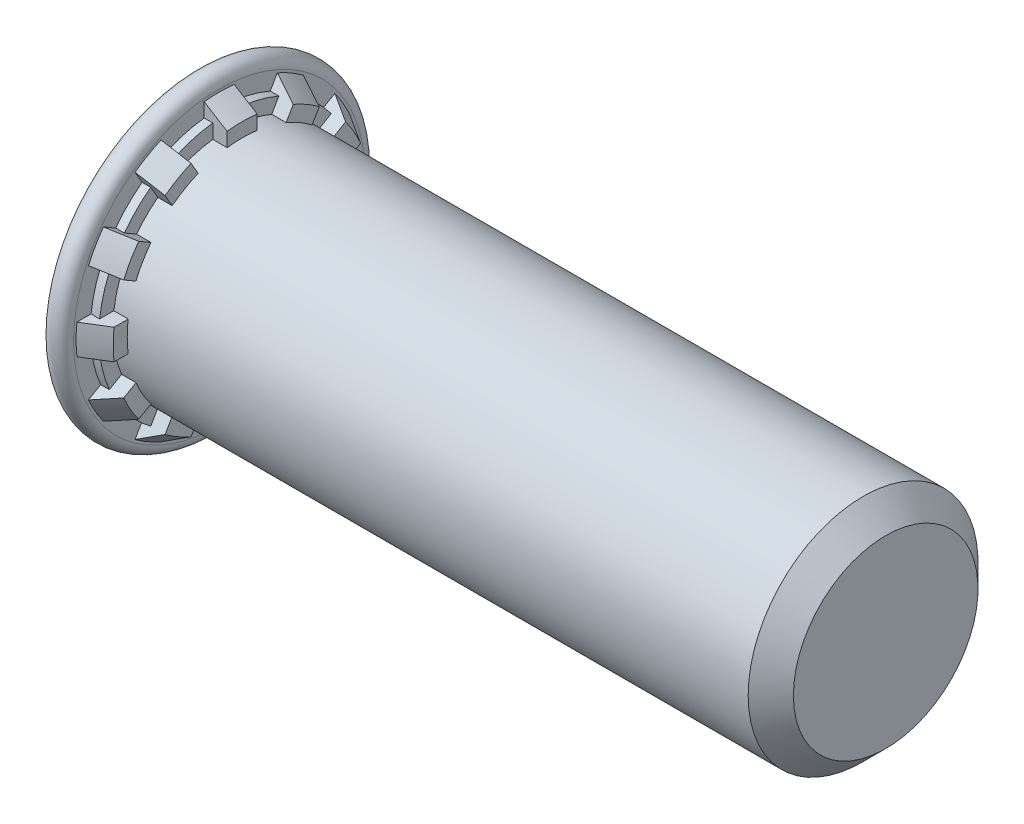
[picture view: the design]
ISO-10303-21;
HEADER;
FILE_DESCRIPTION(('STEP AP214'),'2;1');
FILE_NAME('part.step','',(''),(''),'','','');
FILE_SCHEMA(('AUTOMOTIVE_DESIGN { 1 0 10303 214 1 1 1 1 }'));
ENDSEC;
DATA;
#1=APPLICATION_CONTEXT('core data for automotive mechanical design processes');
#2=APPLICATION_PROTOCOL_DEFINITION('international standard','automotive_design',2000,#1);
#3=PRODUCT_CONTEXT('',#1,'mechanical');
#4=PRODUCT('Part','Part','',(#3));
#5=PRODUCT_RELATED_PRODUCT_CATEGORY('part','',(#4));
#6=PRODUCT_DEFINITION_FORMATION('','',#4);
#7=PRODUCT_DEFINITION_CONTEXT('part definition',#1,'design');
#8=PRODUCT_DEFINITION('design','',#6,#7);
#9=PRODUCT_DEFINITION_SHAPE('','',#8);
#10=(LENGTH_UNIT() NAMED_UNIT(*) SI_UNIT(.MILLI.,.METRE.));
#11=(NAMED_UNIT(*) PLANE_ANGLE_UNIT() SI_UNIT($,.RADIAN.));
#12=(NAMED_UNIT(*) SI_UNIT($,.STERADIAN.) SOLID_ANGLE_UNIT());
#13=UNCERTAINTY_MEASURE_WITH_UNIT(LENGTH_MEASURE(1.E-05),#10,'distance_accuracy_value','');
#14=(GEOMETRIC_REPRESENTATION_CONTEXT(3) GLOBAL_UNCERTAINTY_ASSIGNED_CONTEXT((#13)) GLOBAL_UNIT_ASSIGNED_CONTEXT((#10,
#11,#12)) REPRESENTATION_CONTEXT('',''));
#15=CARTESIAN_POINT('',(0.,0.,0.));
#16=DIRECTION('',(0.,0.,1.));
#17=DIRECTION('',(1.,0.,0.));
#18=AXIS2_PLACEMENT_3D('',#15,#16,#17);
#19=CARTESIAN_POINT('',(0.6,0.,0.));
#20=DIRECTION('',(-1.,0.,0.));
#21=DIRECTION('',(0.,0.,1.));
#22=AXIS2_PLACEMENT_3D('',#19,#20,#21);
#23=CONICAL_SURFACE('',#22,3.735,0.54956001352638);
#24=CARTESIAN_POINT('',(0.6,0.,0.));
#25=DIRECTION('',(-1.,0.,0.));
#26=DIRECTION('',(0.,0.,1.));
#27=AXIS2_PLACEMENT_3D('',#24,#25,#26);
#28=CIRCLE('',#27,3.735);
#29=CARTESIAN_POINT('',(0.6,3.02098991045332,2.19632533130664));
#30=VERTEX_POINT('',#29);
#31=CARTESIAN_POINT('',(0.6,3.41256848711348,1.51809134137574));
#32=VERTEX_POINT('',#31);
#33=EDGE_CURVE('E963',#30,#32,#28,.T.);
#34=ORIENTED_EDGE('',*,*,#33,.F.);
#35=CARTESIAN_POINT('',(1.2002,2.70066079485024,2.01138323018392));
#36=CARTESIAN_POINT('',(1.07508025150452,2.76747981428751,2.04996120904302));
#37=CARTESIAN_POINT('',(0.94994691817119,2.83427974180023,2.08852816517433));
#38=CARTESIAN_POINT('',(0.74980487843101,2.941079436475,2.15018899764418));
#39=CARTESIAN_POINT('',(0.67480487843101,2.98109143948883,2.17328993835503));
#40=CARTESIAN_POINT('',(0.5998,3.0210965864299,2.19638692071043));
#41=B_SPLINE_CURVE_WITH_KNOTS('',3,(#35,#36,#37,#38,#39,#40),.UNSPECIFIED.,.F.,.F.,(4,2,4),(0.,
0.44098970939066,0.705255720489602),.UNSPECIFIED.);
#42=CARTESIAN_POINT('',(1.2,2.70076760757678,2.01144489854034));
#43=VERTEX_POINT('',#42);
#44=EDGE_CURVE('E964',#43,#30,#41,.T.);
#45=ORIENTED_EDGE('',*,*,#44,.F.);
#46=CARTESIAN_POINT('',(1.2,0.,0.));
#47=DIRECTION('',(-1.,0.,0.));
#48=DIRECTION('',(0.,0.,1.));
#49=AXIS2_PLACEMENT_3D('',#46,#47,#48);
#50=CIRCLE('',#49,3.3675);
#51=CARTESIAN_POINT('',(1.2,3.09234618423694,1.33321090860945));
#52=VERTEX_POINT('',#51);
#53=EDGE_CURVE('E1232',#43,#52,#50,.T.);
#54=ORIENTED_EDGE('',*,*,#53,.T.);
#55=CARTESIAN_POINT('',(0.5998,3.41267516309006,1.51815293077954));
#56=CARTESIAN_POINT('',(0.67480487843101,3.37267001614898,1.49505594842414));
#57=CARTESIAN_POINT('',(0.74980487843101,3.33265801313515,1.47195500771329));
#58=CARTESIAN_POINT('',(0.94994691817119,3.22585831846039,1.41029417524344));
#59=CARTESIAN_POINT('',(1.07508025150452,3.15905839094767,1.37172721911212));
#60=CARTESIAN_POINT('',(1.2002,3.0922393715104,1.33314924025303));
#61=B_SPLINE_CURVE_WITH_KNOTS('',3,(#55,#56,#57,#58,#59,#60),.UNSPECIFIED.,.F.,.F.,(4,2,4),(0.,
0.264266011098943,0.705255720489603),.UNSPECIFIED.);
#62=EDGE_CURVE('E855',#32,#52,#61,.T.);
#63=ORIENTED_EDGE('',*,*,#62,.F.);
#64=EDGE_LOOP('',(#34,#45,#54,#63));
#65=FACE_BOUND('',#64,.T.);
#66=ADVANCED_FACE('F39',(#65),#23,.T.);
#67=CARTESIAN_POINT('',(0.5998,2.19638692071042,3.02109658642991));
#68=CARTESIAN_POINT('',(0.674804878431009,2.17328993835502,2.98109143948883));
#69=CARTESIAN_POINT('',(0.74980487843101,2.15018899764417,2.941079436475));
#70=CARTESIAN_POINT('',(0.94994691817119,2.08852816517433,2.83427974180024));
#71=CARTESIAN_POINT('',(1.07508025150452,2.04996120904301,2.76747981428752));
#72=CARTESIAN_POINT('',(1.2002,2.01138323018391,2.70066079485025));
#73=B_SPLINE_CURVE_WITH_KNOTS('',3,(#67,#68,#69,#70,#71,#72),.UNSPECIFIED.,.F.,.F.,(4,2,4),(0.,
0.264266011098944,0.705255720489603),.UNSPECIFIED.);
#74=CARTESIAN_POINT('',(0.6,2.19632533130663,3.02098991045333));
#75=VERTEX_POINT('',#74);
#76=CARTESIAN_POINT('',(1.2,2.01144489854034,2.70076760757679));
#77=VERTEX_POINT('',#76);
#78=EDGE_CURVE('E1268',#75,#77,#73,.T.);
#79=ORIENTED_EDGE('',*,*,#78,.F.);
#80=CARTESIAN_POINT('',(0.6,1.51809134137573,3.41256848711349));
#81=VERTEX_POINT('',#80);
#82=EDGE_CURVE('E501',#81,#75,#28,.T.);
#83=ORIENTED_EDGE('',*,*,#82,.F.);
#84=CARTESIAN_POINT('',(1.2002,1.33314924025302,3.0922393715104));
#85=CARTESIAN_POINT('',(1.07508025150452,1.37172721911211,3.15905839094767));
#86=CARTESIAN_POINT('',(0.94994691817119,1.41029417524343,3.22585831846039));
#87=CARTESIAN_POINT('',(0.749804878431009,1.47195500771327,3.33265801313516));
#88=CARTESIAN_POINT('',(0.674804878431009,1.49505594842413,3.37267001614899));
#89=CARTESIAN_POINT('',(0.5998,1.51815293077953,3.41267516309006));
#90=B_SPLINE_CURVE_WITH_KNOTS('',3,(#84,#85,#86,#87,#88,#89),.UNSPECIFIED.,.F.,.F.,(4,2,4),(0.,
0.440989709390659,0.705255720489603),.UNSPECIFIED.);
#91=CARTESIAN_POINT('',(1.2,1.33321090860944,3.09234618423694));
#92=VERTEX_POINT('',#91);
#93=EDGE_CURVE('E1013',#92,#81,#90,.T.);
#94=ORIENTED_EDGE('',*,*,#93,.F.);
#95=EDGE_CURVE('E1237',#92,#77,#50,.T.);
#96=ORIENTED_EDGE('',*,*,#95,.T.);
#97=EDGE_LOOP('',(#79,#83,#94,#96));
#98=FACE_BOUND('',#97,.T.);
#99=ADVANCED_FACE('F952',(#98),#23,.T.);
#100=CARTESIAN_POINT('',(-0.296527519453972,0.391578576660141,4.26618998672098));
#101=CARTESIAN_POINT('',(-0.286159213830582,0.391578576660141,4.25981269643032));
#102=CARTESIAN_POINT('',(-0.275790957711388,0.391578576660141,4.25343532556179));
#103=CARTESIAN_POINT('',(0.213231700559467,0.391578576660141,3.95263889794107));
#104=CARTESIAN_POINT('',(0.691778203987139,0.391578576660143,3.65804424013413));
#105=CARTESIAN_POINT('',(1.40926693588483,0.391578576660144,3.21561509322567));
#106=CARTESIAN_POINT('',(1.64837471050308,0.391578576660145,3.0680491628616));
#107=CARTESIAN_POINT('',(2.12640919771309,0.391578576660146,2.77262408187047));
#108=CARTESIAN_POINT('',(2.36533591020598,0.391578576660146,2.62476493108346));
#109=CARTESIAN_POINT('',(2.60413661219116,0.391578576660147,2.47670216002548));
#110=B_SPLINE_CURVE_WITH_KNOTS('',3,(#100,#101,#102,#103,#104,#105,#106,#107,#108,#109),
.UNSPECIFIED.,.F.,.F.,(4,2,2,2,4),(0.,0.0365177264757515,1.72238057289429,2.56531223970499,
3.40824436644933),.UNSPECIFIED.);
#111=CARTESIAN_POINT('',(0.6,0.391578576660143,3.71441667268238));
#112=VERTEX_POINT('',#111);
#113=CARTESIAN_POINT('',(1.2,0.391578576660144,3.34465580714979));
#114=VERTEX_POINT('',#113);
#115=EDGE_CURVE('E1009',#112,#114,#110,.T.);
#116=ORIENTED_EDGE('',*,*,#115,.F.);
#117=CARTESIAN_POINT('',(0.6,-0.391578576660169,3.71441667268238));
#118=VERTEX_POINT('',#117);
#119=EDGE_CURVE('E970',#118,#112,#28,.T.);
#120=ORIENTED_EDGE('',*,*,#119,.F.);
#121=CARTESIAN_POINT('',(2.60413661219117,-0.391578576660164,2.47670216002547));
#122=CARTESIAN_POINT('',(2.36533591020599,-0.391578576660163,2.62476493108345));
#123=CARTESIAN_POINT('',(2.12640919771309,-0.391578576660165,2.77262408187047));
#124=CARTESIAN_POINT('',(1.64837471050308,-0.391578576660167,3.0680491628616));
#125=CARTESIAN_POINT('',(1.40926693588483,-0.391578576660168,3.21561509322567));
#126=CARTESIAN_POINT('',(0.691778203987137,-0.391578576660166,3.65804424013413));
#127=CARTESIAN_POINT('',(0.213231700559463,-0.391578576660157,3.95263889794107));
#128=CARTESIAN_POINT('',(-0.275790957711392,-0.391578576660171,4.25343532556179));
#129=CARTESIAN_POINT('',(-0.286159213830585,-0.391578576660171,4.25981269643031));
#130=CARTESIAN_POINT('',(-0.296527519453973,-0.391578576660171,4.26618998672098));
#131=B_SPLINE_CURVE_WITH_KNOTS('',3,(#121,#122,#123,#124,#125,#126,#127,#128,#129,#130),
.UNSPECIFIED.,.F.,.F.,(4,2,2,2,4),(0.,0.842932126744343,1.68586379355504,3.37172663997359,
3.40824436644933),.UNSPECIFIED.);
#132=CARTESIAN_POINT('',(1.2,-0.391578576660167,3.34465580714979));
#133=VERTEX_POINT('',#132);
#134=EDGE_CURVE('E1007',#133,#118,#131,.T.);
#135=ORIENTED_EDGE('',*,*,#134,.F.);
#136=EDGE_CURVE('E1010',#133,#114,#50,.T.);
#137=ORIENTED_EDGE('',*,*,#136,.T.);
#138=EDGE_LOOP('',(#116,#120,#135,#137));
#139=FACE_BOUND('',#138,.T.);
#140=ADVANCED_FACE('F958',(#139),#23,.T.);
#141=CARTESIAN_POINT('',(0.5998,-1.51815293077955,3.41267516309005));
#142=CARTESIAN_POINT('',(0.67480487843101,-1.49505594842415,3.37267001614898));
#143=CARTESIAN_POINT('',(0.74980487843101,-1.4719550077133,3.33265801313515));
#144=CARTESIAN_POINT('',(0.94994691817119,-1.41029417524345,3.22585831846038));
#145=CARTESIAN_POINT('',(1.07508025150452,-1.37172721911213,3.15905839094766));
#146=CARTESIAN_POINT('',(1.2002,-1.33314924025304,3.09223937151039));
#147=B_SPLINE_CURVE_WITH_KNOTS('',3,(#141,#142,#143,#144,#145,#146),.UNSPECIFIED.,.F.,.F.,(4,2,
4),(0.,0.264266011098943,0.705255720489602),.UNSPECIFIED.);
#148=CARTESIAN_POINT('',(0.6,-1.51809134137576,3.41256848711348));
#149=VERTEX_POINT('',#148);
#150=CARTESIAN_POINT('',(1.2,-1.33321090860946,3.09234618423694));
#151=VERTEX_POINT('',#150);
#152=EDGE_CURVE('E1029',#149,#151,#147,.T.);
#153=ORIENTED_EDGE('',*,*,#152,.F.);
#154=CARTESIAN_POINT('',(0.6,-2.19632533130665,3.02098991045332));
#155=VERTEX_POINT('',#154);
#156=EDGE_CURVE('E995',#155,#149,#28,.T.);
#157=ORIENTED_EDGE('',*,*,#156,.F.);
#158=CARTESIAN_POINT('',(1.2002,-2.01138323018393,2.70066079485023));
#159=CARTESIAN_POINT('',(1.07508025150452,-2.04996120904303,2.7674798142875));
#160=CARTESIAN_POINT('',(0.949946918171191,-2.08852816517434,2.83427974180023));
#161=CARTESIAN_POINT('',(0.74980487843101,-2.15018899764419,2.94107943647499));
#162=CARTESIAN_POINT('',(0.67480487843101,-2.17328993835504,2.98109143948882));
#163=CARTESIAN_POINT('',(0.5998,-2.19638692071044,3.02109658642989));
#164=B_SPLINE_CURVE_WITH_KNOTS('',3,(#158,#159,#160,#161,#162,#163),.UNSPECIFIED.,.F.,.F.,(4,2,
4),(0.,0.44098970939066,0.705255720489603),.UNSPECIFIED.);
#165=CARTESIAN_POINT('',(1.2,-2.01144489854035,2.70076760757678));
#166=VERTEX_POINT('',#165);
#167=EDGE_CURVE('E1081',#166,#155,#164,.T.);
#168=ORIENTED_EDGE('',*,*,#167,.F.);
#169=EDGE_CURVE('E1340',#166,#151,#50,.T.);
#170=ORIENTED_EDGE('',*,*,#169,.T.);
#171=EDGE_LOOP('',(#153,#157,#168,#170));
#172=FACE_BOUND('',#171,.T.);
#173=ADVANCED_FACE('F1475',(#172),#23,.T.);
#174=CARTESIAN_POINT('',(0.5998,-3.02109658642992,2.19638692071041));
#175=CARTESIAN_POINT('',(0.67480487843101,-2.98109143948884,2.17328993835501));
#176=CARTESIAN_POINT('',(0.74980487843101,-2.94107943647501,2.15018899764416));
#177=CARTESIAN_POINT('',(0.94994691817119,-2.83427974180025,2.08852816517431));
#178=CARTESIAN_POINT('',(1.07508025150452,-2.76747981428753,2.049961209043));
#179=CARTESIAN_POINT('',(1.2002,-2.70066079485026,2.0113832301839));
#180=B_SPLINE_CURVE_WITH_KNOTS('',3,(#174,#175,#176,#177,#178,#179),.UNSPECIFIED.,.F.,.F.,(4,2,
4),(0.,0.264266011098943,0.705255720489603),.UNSPECIFIED.);
#181=CARTESIAN_POINT('',(0.6,-3.02098991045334,2.19632533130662));
#182=VERTEX_POINT('',#181);
#183=CARTESIAN_POINT('',(1.2,-2.7007676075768,2.01144489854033));
#184=VERTEX_POINT('',#183);
#185=EDGE_CURVE('E1075',#182,#184,#180,.T.);
#186=ORIENTED_EDGE('',*,*,#185,.F.);
#187=CARTESIAN_POINT('',(0.6,-3.41256848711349,1.51809134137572));
#188=VERTEX_POINT('',#187);
#189=EDGE_CURVE('E992',#188,#182,#28,.T.);
#190=ORIENTED_EDGE('',*,*,#189,.F.);
#191=CARTESIAN_POINT('',(1.2002,-3.09223937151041,1.33314924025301));
#192=CARTESIAN_POINT('',(1.07508025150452,-3.15905839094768,1.3717272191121));
#193=CARTESIAN_POINT('',(0.949946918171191,-3.2258583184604,1.41029417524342));
#194=CARTESIAN_POINT('',(0.74980487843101,-3.33265801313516,1.47195500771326));
#195=CARTESIAN_POINT('',(0.67480487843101,-3.37267001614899,1.49505594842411));
#196=CARTESIAN_POINT('',(0.5998,-3.41267516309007,1.51815293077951));
#197=B_SPLINE_CURVE_WITH_KNOTS('',3,(#191,#192,#193,#194,#195,#196),.UNSPECIFIED.,.F.,.F.,(4,2,
4),(0.,0.44098970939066,0.705255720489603),.UNSPECIFIED.);
#198=CARTESIAN_POINT('',(1.2,-3.09234618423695,1.33321090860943));
#199=VERTEX_POINT('',#198);
#200=EDGE_CURVE('E1116',#199,#188,#197,.T.);
#201=ORIENTED_EDGE('',*,*,#200,.F.);
#202=EDGE_CURVE('E1335',#199,#184,#50,.T.);
#203=ORIENTED_EDGE('',*,*,#202,.T.);
#204=EDGE_LOOP('',(#186,#190,#201,#203));
#205=FACE_BOUND('',#204,.T.);
#206=ADVANCED_FACE('F1446',(#205),#23,.T.);
#207=CARTESIAN_POINT('',(-0.571392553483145,-4.43522558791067,0.391578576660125));
#208=CARTESIAN_POINT('',(-0.33204367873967,-4.28805118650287,0.391578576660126));
#209=CARTESIAN_POINT('',(-0.092717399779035,-4.1408400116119,0.391578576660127));
#210=CARTESIAN_POINT('',(0.385864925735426,-3.84630382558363,0.391578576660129));
#211=CARTESIAN_POINT('',(0.62512097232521,-3.69897881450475,0.39157857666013));
#212=CARTESIAN_POINT('',(1.10353812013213,-3.404174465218,0.391578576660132));
#213=CARTESIAN_POINT('',(1.34269922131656,-3.25669512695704,0.391578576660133));
#214=CARTESIAN_POINT('',(1.82087179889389,-2.96149383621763,0.391578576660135));
#215=CARTESIAN_POINT('',(2.05988327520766,-2.81377188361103,0.391578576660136));
#216=CARTESIAN_POINT('',(2.29879251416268,-2.66588453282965,0.391578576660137));
#217=B_SPLINE_CURVE_WITH_KNOTS('',3,(#207,#208,#209,#210,#211,#212,#213,#214,#215,#216),
.UNSPECIFIED.,.F.,.F.,(4,2,2,2,4),(0.,0.84293162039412,1.68586280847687,2.52879428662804,
3.3717262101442),.UNSPECIFIED.);
#218=CARTESIAN_POINT('',(0.6,-3.71441667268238,0.39157857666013));
#219=VERTEX_POINT('',#218);
#220=CARTESIAN_POINT('',(1.2,-3.34465580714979,0.391578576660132));
#221=VERTEX_POINT('',#220);
#222=EDGE_CURVE('E1110',#219,#221,#217,.T.);
#223=ORIENTED_EDGE('',*,*,#222,.F.);
#224=CARTESIAN_POINT('',(0.6,-3.71441667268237,-0.391578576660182));
#225=VERTEX_POINT('',#224);
#226=EDGE_CURVE('E989',#225,#219,#28,.T.);
#227=ORIENTED_EDGE('',*,*,#226,.F.);
#228=CARTESIAN_POINT('',(2.29879251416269,-2.66588453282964,-0.391578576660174));
#229=CARTESIAN_POINT('',(2.05988327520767,-2.81377188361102,-0.391578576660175));
#230=CARTESIAN_POINT('',(1.8208717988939,-2.96149383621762,-0.391578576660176));
#231=CARTESIAN_POINT('',(1.34269922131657,-3.25669512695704,-0.391578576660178));
#232=CARTESIAN_POINT('',(1.10353812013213,-3.404174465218,-0.391578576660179));
#233=CARTESIAN_POINT('',(0.625120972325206,-3.69897881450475,-0.391578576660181));
#234=CARTESIAN_POINT('',(0.385864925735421,-3.84630382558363,-0.391578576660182));
#235=CARTESIAN_POINT('',(-0.0927173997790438,-4.1408400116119,-0.391578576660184));
#236=CARTESIAN_POINT('',(-0.33204367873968,-4.28805118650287,-0.391578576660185));
#237=CARTESIAN_POINT('',(-0.571392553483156,-4.43522558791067,-0.391578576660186));
#238=B_SPLINE_CURVE_WITH_KNOTS('',3,(#228,#229,#230,#231,#232,#233,#234,#235,#236,#237),
.UNSPECIFIED.,.F.,.F.,(4,2,2,2,4),(0.,0.842931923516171,1.68586340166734,2.5287945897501,
3.37172621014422),.UNSPECIFIED.);
#239=CARTESIAN_POINT('',(1.2,-3.34465580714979,-0.391578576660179));
#240=VERTEX_POINT('',#239);
#241=EDGE_CURVE('E1129',#240,#225,#238,.T.);
#242=ORIENTED_EDGE('',*,*,#241,.F.);
#243=EDGE_CURVE('E1330',#240,#221,#50,.T.);
#244=ORIENTED_EDGE('',*,*,#243,.T.);
#245=EDGE_LOOP('',(#223,#227,#242,#244));
#246=FACE_BOUND('',#245,.T.);
#247=ADVANCED_FACE('F1442',(#246),#23,.T.);
#248=CARTESIAN_POINT('',(0.5998,-3.41267516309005,-1.51815293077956));
#249=CARTESIAN_POINT('',(0.674804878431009,-3.37267001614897,-1.49505594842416));
#250=CARTESIAN_POINT('',(0.74980487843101,-3.33265801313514,-1.47195500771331));
#251=CARTESIAN_POINT('',(0.94994691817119,-3.22585831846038,-1.41029417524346));
#252=CARTESIAN_POINT('',(1.07508025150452,-3.15905839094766,-1.37172721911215));
#253=CARTESIAN_POINT('',(1.2002,-3.09223937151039,-1.33314924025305));
#254=B_SPLINE_CURVE_WITH_KNOTS('',3,(#248,#249,#250,#251,#252,#253),.UNSPECIFIED.,.F.,.F.,(4,2,
4),(0.,0.264266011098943,0.705255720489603),.UNSPECIFIED.);
#255=CARTESIAN_POINT('',(0.6,-3.41256848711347,-1.51809134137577));
#256=VERTEX_POINT('',#255);
#257=CARTESIAN_POINT('',(1.2,-3.09234618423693,-1.33321090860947));
#258=VERTEX_POINT('',#257);
#259=EDGE_CURVE('E1122',#256,#258,#254,.T.);
#260=ORIENTED_EDGE('',*,*,#259,.F.);
#261=CARTESIAN_POINT('',(0.6,-3.02098991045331,-2.19632533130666));
#262=VERTEX_POINT('',#261);
#263=EDGE_CURVE('E986',#262,#256,#28,.T.);
#264=ORIENTED_EDGE('',*,*,#263,.F.);
#265=CARTESIAN_POINT('',(1.2002,-2.70066079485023,-2.01138323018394));
#266=CARTESIAN_POINT('',(1.07508025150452,-2.7674798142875,-2.04996120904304));
#267=CARTESIAN_POINT('',(0.949946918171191,-2.83427974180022,-2.08852816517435));
#268=CARTESIAN_POINT('',(0.74980487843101,-2.94107943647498,-2.1501889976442));
#269=CARTESIAN_POINT('',(0.67480487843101,-2.98109143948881,-2.17328993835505));
#270=CARTESIAN_POINT('',(0.5998,-3.02109658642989,-2.19638692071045));
#271=B_SPLINE_CURVE_WITH_KNOTS('',3,(#265,#266,#267,#268,#269,#270),.UNSPECIFIED.,.F.,.F.,(4,2,
4),(0.,0.44098970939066,0.705255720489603),.UNSPECIFIED.);
#272=CARTESIAN_POINT('',(1.2,-2.70076760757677,-2.01144489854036));
#273=VERTEX_POINT('',#272);
#274=EDGE_CURVE('E1164',#273,#262,#271,.T.);
#275=ORIENTED_EDGE('',*,*,#274,.F.);
#276=EDGE_CURVE('E1325',#273,#258,#50,.T.);
#277=ORIENTED_EDGE('',*,*,#276,.T.);
#278=EDGE_LOOP('',(#260,#264,#275,#277));
#279=FACE_BOUND('',#278,.T.);
#280=ADVANCED_FACE('F1438',(#279),#23,.T.);
#281=CARTESIAN_POINT('',(0.5998,-2.1963869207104,-3.02109658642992));
#282=CARTESIAN_POINT('',(0.674804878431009,-2.173289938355,-2.98109143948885));
#283=CARTESIAN_POINT('',(0.74980487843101,-2.15018899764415,-2.94107943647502));
#284=CARTESIAN_POINT('',(0.94994691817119,-2.08852816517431,-2.83427974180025));
#285=CARTESIAN_POINT('',(1.07508025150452,-2.04996120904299,-2.76747981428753));
#286=CARTESIAN_POINT('',(1.2002,-2.01138323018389,-2.70066079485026));
#287=B_SPLINE_CURVE_WITH_KNOTS('',3,(#281,#282,#283,#284,#285,#286),.UNSPECIFIED.,.F.,.F.,(4,2,
4),(0.,0.264266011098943,0.705255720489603),.UNSPECIFIED.);
#288=CARTESIAN_POINT('',(0.6,-2.19632533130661,-3.02098991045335));
#289=VERTEX_POINT('',#288);
#290=CARTESIAN_POINT('',(1.2,-2.01144489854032,-2.7007676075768));
#291=VERTEX_POINT('',#290);
#292=EDGE_CURVE('E1158',#289,#291,#287,.T.);
#293=ORIENTED_EDGE('',*,*,#292,.F.);
#294=CARTESIAN_POINT('',(0.6,-1.51809134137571,-3.4125684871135));
#295=VERTEX_POINT('',#294);
#296=EDGE_CURVE('E983',#295,#289,#28,.T.);
#297=ORIENTED_EDGE('',*,*,#296,.F.);
#298=CARTESIAN_POINT('',(1.2002,-1.333149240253,-3.09223937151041));
#299=CARTESIAN_POINT('',(1.07508025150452,-1.37172721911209,-3.15905839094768));
#300=CARTESIAN_POINT('',(0.949946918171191,-1.41029417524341,-3.2258583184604));
#301=CARTESIAN_POINT('',(0.74980487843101,-1.47195500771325,-3.33265801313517));
#302=CARTESIAN_POINT('',(0.67480487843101,-1.4950559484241,-3.372670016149));
#303=CARTESIAN_POINT('',(0.5998,-1.5181529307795,-3.41267516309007));
#304=B_SPLINE_CURVE_WITH_KNOTS('',3,(#298,#299,#300,#301,#302,#303),.UNSPECIFIED.,.F.,.F.,(4,2,
4),(0.,0.44098970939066,0.705255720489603),.UNSPECIFIED.);
#305=CARTESIAN_POINT('',(1.2,-1.33321090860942,-3.09234618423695));
#306=VERTEX_POINT('',#305);
#307=EDGE_CURVE('E1177',#306,#295,#304,.T.);
#308=ORIENTED_EDGE('',*,*,#307,.F.);
#309=EDGE_CURVE('E1323',#306,#291,#50,.T.);
#310=ORIENTED_EDGE('',*,*,#309,.T.);
#311=EDGE_LOOP('',(#293,#297,#308,#310));
#312=FACE_BOUND('',#311,.T.);
#313=ADVANCED_FACE('F1419',(#312),#23,.T.);
#314=CARTESIAN_POINT('',(-0.571392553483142,-0.391578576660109,-4.43522558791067));
#315=CARTESIAN_POINT('',(-0.332043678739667,-0.391578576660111,-4.28805118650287));
#316=CARTESIAN_POINT('',(-0.0927173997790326,-0.391578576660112,-4.1408400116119));
#317=CARTESIAN_POINT('',(0.385864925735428,-0.391578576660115,-3.84630382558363));
#318=CARTESIAN_POINT('',(0.625120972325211,-0.391578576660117,-3.69897881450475));
#319=CARTESIAN_POINT('',(1.10353812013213,-0.39157857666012,-3.404174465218));
#320=CARTESIAN_POINT('',(1.34269922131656,-0.391578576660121,-3.25669512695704));
#321=CARTESIAN_POINT('',(1.82087179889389,-0.391578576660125,-2.96149383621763));
#322=CARTESIAN_POINT('',(2.05988327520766,-0.391578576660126,-2.81377188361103));
#323=CARTESIAN_POINT('',(2.29879251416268,-0.391578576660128,-2.66588453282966));
#324=B_SPLINE_CURVE_WITH_KNOTS('',3,(#314,#315,#316,#317,#318,#319,#320,#321,#322,#323),
.UNSPECIFIED.,.F.,.F.,(4,2,2,2,4),(0.,0.842931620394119,1.68586280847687,2.52879428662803,
3.3717262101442),.UNSPECIFIED.);
#325=CARTESIAN_POINT('',(0.6,-0.391578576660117,-3.71441667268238));
#326=VERTEX_POINT('',#325);
#327=CARTESIAN_POINT('',(1.2,-0.391578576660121,-3.34465580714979));
#328=VERTEX_POINT('',#327);
#329=EDGE_CURVE('E1170',#326,#328,#324,.T.);
#330=ORIENTED_EDGE('',*,*,#329,.F.);
#331=CARTESIAN_POINT('',(0.6,0.391578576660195,-3.71441667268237));
#332=VERTEX_POINT('',#331);
#333=EDGE_CURVE('E980',#332,#326,#28,.T.);
#334=ORIENTED_EDGE('',*,*,#333,.F.);
#335=CARTESIAN_POINT('',(2.29879251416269,0.391578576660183,-2.66588453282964));
#336=CARTESIAN_POINT('',(2.05988327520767,0.391578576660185,-2.81377188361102));
#337=CARTESIAN_POINT('',(1.8208717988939,0.391578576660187,-2.96149383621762));
#338=CARTESIAN_POINT('',(1.34269922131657,0.39157857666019,-3.25669512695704));
#339=CARTESIAN_POINT('',(1.10353812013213,0.391578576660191,-3.404174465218));
#340=CARTESIAN_POINT('',(0.625120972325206,0.391578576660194,-3.69897881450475));
#341=CARTESIAN_POINT('',(0.38586492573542,0.391578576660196,-3.84630382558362));
#342=CARTESIAN_POINT('',(-0.0927173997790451,0.391578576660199,-4.1408400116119));
#343=CARTESIAN_POINT('',(-0.332043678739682,0.3915785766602,-4.28805118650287));
#344=CARTESIAN_POINT('',(-0.571392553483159,0.391578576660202,-4.43522558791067));
#345=B_SPLINE_CURVE_WITH_KNOTS('',3,(#335,#336,#337,#338,#339,#340,#341,#342,#343,#344),
.UNSPECIFIED.,.F.,.F.,(4,2,2,2,4),(0.,0.842931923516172,1.68586340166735,2.5287945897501,
3.37172621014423),.UNSPECIFIED.);
#346=CARTESIAN_POINT('',(1.2,0.391578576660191,-3.34465580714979));
#347=VERTEX_POINT('',#346);
#348=EDGE_CURVE('E1209',#347,#332,#345,.T.);
#349=ORIENTED_EDGE('',*,*,#348,.F.);
#350=EDGE_CURVE('E1235',#347,#328,#50,.T.);
#351=ORIENTED_EDGE('',*,*,#350,.T.);
#352=EDGE_LOOP('',(#330,#334,#349,#351));
#353=FACE_BOUND('',#352,.T.);
#354=ADVANCED_FACE('F1430',(#353),#23,.T.);
#355=CARTESIAN_POINT('',(0.5998,1.51815293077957,-3.41267516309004));
#356=CARTESIAN_POINT('',(0.67480487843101,1.49505594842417,-3.37267001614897));
#357=CARTESIAN_POINT('',(0.74980487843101,1.47195500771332,-3.33265801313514));
#358=CARTESIAN_POINT('',(0.94994691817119,1.41029417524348,-3.22585831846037));
#359=CARTESIAN_POINT('',(1.07508025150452,1.37172721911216,-3.15905839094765));
#360=CARTESIAN_POINT('',(1.2002,1.33314924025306,-3.09223937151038));
#361=B_SPLINE_CURVE_WITH_KNOTS('',3,(#355,#356,#357,#358,#359,#360),.UNSPECIFIED.,.F.,.F.,(4,2,
4),(0.,0.264266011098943,0.705255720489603),.UNSPECIFIED.);
#362=CARTESIAN_POINT('',(0.6,1.51809134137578,-3.41256848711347));
#363=VERTEX_POINT('',#362);
#364=CARTESIAN_POINT('',(1.2,1.33321090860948,-3.09234618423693));
#365=VERTEX_POINT('',#364);
#366=EDGE_CURVE('E1204',#363,#365,#361,.T.);
#367=ORIENTED_EDGE('',*,*,#366,.F.);
#368=CARTESIAN_POINT('',(0.6,2.19632533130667,-3.0209899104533));
#369=VERTEX_POINT('',#368);
#370=EDGE_CURVE('E972',#369,#363,#28,.T.);
#371=ORIENTED_EDGE('',*,*,#370,.F.);
#372=CARTESIAN_POINT('',(1.2002,2.01138323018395,-2.70066079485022));
#373=CARTESIAN_POINT('',(1.07508025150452,2.04996120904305,-2.76747981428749));
#374=CARTESIAN_POINT('',(0.94994691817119,2.08852816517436,-2.83427974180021));
#375=CARTESIAN_POINT('',(0.74980487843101,2.15018899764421,-2.94107943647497));
#376=CARTESIAN_POINT('',(0.67480487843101,2.17328993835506,-2.9810914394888));
#377=CARTESIAN_POINT('',(0.5998,2.19638692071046,-3.02109658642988));
#378=B_SPLINE_CURVE_WITH_KNOTS('',3,(#372,#373,#374,#375,#376,#377),.UNSPECIFIED.,.F.,.F.,(4,2,
4),(0.,0.440989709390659,0.705255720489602),.UNSPECIFIED.);
#379=CARTESIAN_POINT('',(1.2,2.01144489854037,-2.70076760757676));
#380=VERTEX_POINT('',#379);
#381=EDGE_CURVE('E662',#380,#369,#378,.T.);
#382=ORIENTED_EDGE('',*,*,#381,.F.);
#383=EDGE_CURVE('E1231',#380,#365,#50,.T.);
#384=ORIENTED_EDGE('',*,*,#383,.T.);
#385=EDGE_LOOP('',(#367,#371,#382,#384));
#386=FACE_BOUND('',#385,.T.);
#387=ADVANCED_FACE('F1432',(#386),#23,.T.);
#388=CARTESIAN_POINT('',(0.6,3.71441667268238,0.391578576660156));
#389=VERTEX_POINT('',#388);
#390=CARTESIAN_POINT('',(0.6,3.71441667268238,-0.391578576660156));
#391=VERTEX_POINT('',#390);
#392=EDGE_CURVE('E967',#389,#391,#28,.T.);
#393=ORIENTED_EDGE('',*,*,#392,.F.);
#394=CARTESIAN_POINT('',(2.60413661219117,2.47670216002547,0.391578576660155));
#395=CARTESIAN_POINT('',(2.36533591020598,2.62476493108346,0.391578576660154));
#396=CARTESIAN_POINT('',(2.12640919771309,2.77262408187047,0.391578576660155));
#397=CARTESIAN_POINT('',(1.64837471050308,3.0680491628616,0.391578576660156));
#398=CARTESIAN_POINT('',(1.40926693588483,3.21561509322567,0.391578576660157));
#399=CARTESIAN_POINT('',(0.691778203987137,3.65804424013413,0.391578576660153));
#400=CARTESIAN_POINT('',(0.213231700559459,3.95263889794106,0.391578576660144));
#401=CARTESIAN_POINT('',(-0.275790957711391,4.25343532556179,0.391578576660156));
#402=CARTESIAN_POINT('',(-0.286159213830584,4.25981269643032,0.391578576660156));
#403=CARTESIAN_POINT('',(-0.296527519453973,4.26618998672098,0.391578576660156));
#404=B_SPLINE_CURVE_WITH_KNOTS('',3,(#394,#395,#396,#397,#398,#399,#400,#401,#402,#403),
.UNSPECIFIED.,.F.,.F.,(4,2,2,2,4),(0.,0.842932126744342,1.68586379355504,3.37172663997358,
3.40824436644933),.UNSPECIFIED.);
#405=CARTESIAN_POINT('',(1.2,3.34465580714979,0.391578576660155));
#406=VERTEX_POINT('',#405);
#407=EDGE_CURVE('E864',#406,#389,#404,.T.);
#408=ORIENTED_EDGE('',*,*,#407,.F.);
#409=CARTESIAN_POINT('',(1.2,3.34465580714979,-0.391578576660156));
#410=VERTEX_POINT('',#409);
#411=EDGE_CURVE('E1233',#406,#410,#50,.T.);
#412=ORIENTED_EDGE('',*,*,#411,.T.);
#413=CARTESIAN_POINT('',(-0.296527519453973,4.26618998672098,-0.391578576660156));
#414=CARTESIAN_POINT('',(-0.286159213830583,4.25981269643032,-0.391578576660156));
#415=CARTESIAN_POINT('',(-0.27579095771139,4.25343532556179,-0.391578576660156));
#416=CARTESIAN_POINT('',(0.213231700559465,3.95263889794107,-0.391578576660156));
#417=CARTESIAN_POINT('',(0.691778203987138,3.65804424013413,-0.391578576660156));
#418=CARTESIAN_POINT('',(1.40926693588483,3.21561509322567,-0.391578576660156));
#419=CARTESIAN_POINT('',(1.64837471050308,3.0680491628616,-0.391578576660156));
#420=CARTESIAN_POINT('',(2.12640919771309,2.77262408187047,-0.391578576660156));
#421=CARTESIAN_POINT('',(2.36533591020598,2.62476493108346,-0.391578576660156));
#422=CARTESIAN_POINT('',(2.60413661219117,2.47670216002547,-0.391578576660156));
#423=B_SPLINE_CURVE_WITH_KNOTS('',3,(#413,#414,#415,#416,#417,#418,#419,#420,#421,#422),
.UNSPECIFIED.,.F.,.F.,(4,2,2,2,4),(0.,0.0365177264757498,1.72238057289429,2.56531223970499,
3.40824436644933),.UNSPECIFIED.);
#424=EDGE_CURVE('E907',#391,#410,#423,.T.);
#425=ORIENTED_EDGE('',*,*,#424,.F.);
#426=EDGE_LOOP('',(#393,#408,#412,#425));
#427=FACE_BOUND('',#426,.T.);
#428=ADVANCED_FACE('F943',(#427),#23,.T.);
#429=CARTESIAN_POINT('',(1.2,3.3675,0.));
#430=DIRECTION('',(1.,0.,0.));
#431=DIRECTION('',(0.,0.,-1.));
#432=AXIS2_PLACEMENT_3D('',#429,#430,#431);
#433=PLANE('',#432);
#434=DIRECTION('',(0.,-0.499999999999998,-0.86602540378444));
#435=VECTOR('',#434,1.);
#436=CARTESIAN_POINT('',(1.2,1.82628428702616,2.38006002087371));
#437=LINE('',#436,#435);
#438=CARTESIAN_POINT('',(1.2,1.82628428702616,2.38006002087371));
#439=VERTEX_POINT('',#438);
#440=EDGE_CURVE('E653',#77,#439,#437,.T.);
#441=ORIENTED_EDGE('',*,*,#440,.F.);
#442=ORIENTED_EDGE('',*,*,#95,.F.);
#443=DIRECTION('',(0.,0.499999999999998,0.86602540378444));
#444=VECTOR('',#443,1.);
#445=CARTESIAN_POINT('',(1.2,1.14805029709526,2.77163859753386));
#446=LINE('',#445,#444);
#447=CARTESIAN_POINT('',(1.2,1.14805029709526,2.77163859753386));
#448=VERTEX_POINT('',#447);
#449=EDGE_CURVE('E674',#448,#92,#446,.T.);
#450=ORIENTED_EDGE('',*,*,#449,.F.);
#451=CARTESIAN_POINT('',(1.2,0.,0.));
#452=DIRECTION('',(-1.,0.,0.));
#453=DIRECTION('',(0.,0.,1.));
#454=AXIS2_PLACEMENT_3D('',#451,#452,#453);
#455=CIRCLE('',#454,3.);
#456=EDGE_CURVE('E1249',#448,#439,#455,.T.);
#457=ORIENTED_EDGE('',*,*,#456,.T.);
#458=EDGE_LOOP('',(#441,#442,#450,#457));
#459=FACE_BOUND('',#458,.T.);
#460=ADVANCED_FACE('F937',(#459),#433,.T.);
#461=DIRECTION('',(0.,0.,-1.));
#462=VECTOR('',#461,1.);
#463=CARTESIAN_POINT('',(1.2,0.391578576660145,2.97433458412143));
#464=LINE('',#463,#462);
#465=CARTESIAN_POINT('',(1.2,0.391578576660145,2.97433458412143));
#466=VERTEX_POINT('',#465);
#467=EDGE_CURVE('E668',#114,#466,#464,.T.);
#468=ORIENTED_EDGE('',*,*,#467,.F.);
#469=ORIENTED_EDGE('',*,*,#136,.F.);
#470=DIRECTION('',(0.,0.,1.));
#471=VECTOR('',#470,1.);
#472=CARTESIAN_POINT('',(1.2,-0.391578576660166,2.97433458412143));
#473=LINE('',#472,#471);
#474=CARTESIAN_POINT('',(1.2,-0.391578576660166,2.97433458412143));
#475=VERTEX_POINT('',#474);
#476=EDGE_CURVE('E690',#475,#133,#473,.T.);
#477=ORIENTED_EDGE('',*,*,#476,.F.);
#478=EDGE_CURVE('E1377',#475,#466,#455,.T.);
#479=ORIENTED_EDGE('',*,*,#478,.T.);
#480=EDGE_LOOP('',(#468,#469,#477,#479));
#481=FACE_BOUND('',#480,.T.);
#482=ADVANCED_FACE('F946',(#481),#433,.T.);
#483=DIRECTION('',(0.,0.500000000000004,-0.866025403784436));
#484=VECTOR('',#483,1.);
#485=CARTESIAN_POINT('',(1.2,-1.14805029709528,2.77163859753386));
#486=LINE('',#485,#484);
#487=CARTESIAN_POINT('',(1.2,-1.14805029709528,2.77163859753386));
#488=VERTEX_POINT('',#487);
#489=EDGE_CURVE('E684',#151,#488,#486,.T.);
#490=ORIENTED_EDGE('',*,*,#489,.F.);
#491=ORIENTED_EDGE('',*,*,#169,.F.);
#492=DIRECTION('',(0.,-0.500000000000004,0.866025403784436));
#493=VECTOR('',#492,1.);
#494=CARTESIAN_POINT('',(1.2,-1.82628428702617,2.3800600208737));
#495=LINE('',#494,#493);
#496=CARTESIAN_POINT('',(1.2,-1.82628428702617,2.3800600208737));
#497=VERTEX_POINT('',#496);
#498=EDGE_CURVE('E707',#497,#166,#495,.T.);
#499=ORIENTED_EDGE('',*,*,#498,.F.);
#500=EDGE_CURVE('E1379',#497,#488,#455,.T.);
#501=ORIENTED_EDGE('',*,*,#500,.T.);
#502=EDGE_LOOP('',(#490,#491,#499,#501));
#503=FACE_BOUND('',#502,.T.);
#504=ADVANCED_FACE('F1476',(#503),#433,.T.);
#505=DIRECTION('',(0.,0.866025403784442,-0.499999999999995));
#506=VECTOR('',#505,1.);
#507=CARTESIAN_POINT('',(1.2,-2.38006002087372,1.82628428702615));
#508=LINE('',#507,#506);
#509=CARTESIAN_POINT('',(1.2,-2.38006002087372,1.82628428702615));
#510=VERTEX_POINT('',#509);
#511=EDGE_CURVE('E701',#184,#510,#508,.T.);
#512=ORIENTED_EDGE('',*,*,#511,.F.);
#513=ORIENTED_EDGE('',*,*,#202,.F.);
#514=DIRECTION('',(0.,-0.866025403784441,0.499999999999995));
#515=VECTOR('',#514,1.);
#516=CARTESIAN_POINT('',(1.2,-2.77163859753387,1.14805029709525));
#517=LINE('',#516,#515);
#518=CARTESIAN_POINT('',(1.2,-2.77163859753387,1.14805029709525));
#519=VERTEX_POINT('',#518);
#520=EDGE_CURVE('E724',#519,#199,#517,.T.);
#521=ORIENTED_EDGE('',*,*,#520,.F.);
#522=EDGE_CURVE('E1383',#519,#510,#455,.T.);
#523=ORIENTED_EDGE('',*,*,#522,.T.);
#524=EDGE_LOOP('',(#512,#513,#521,#523));
#525=FACE_BOUND('',#524,.T.);
#526=ADVANCED_FACE('F1465',(#525),#433,.T.);
#527=DIRECTION('',(0.,1.,0.));
#528=VECTOR('',#527,1.);
#529=CARTESIAN_POINT('',(1.2,-2.97433458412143,0.391578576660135));
#530=LINE('',#529,#528);
#531=CARTESIAN_POINT('',(1.2,-2.97433458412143,0.391578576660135));
#532=VERTEX_POINT('',#531);
#533=EDGE_CURVE('E718',#221,#532,#530,.T.);
#534=ORIENTED_EDGE('',*,*,#533,.F.);
#535=ORIENTED_EDGE('',*,*,#243,.F.);
#536=DIRECTION('',(0.,-1.,0.));
#537=VECTOR('',#536,1.);
#538=CARTESIAN_POINT('',(1.2,-2.97433458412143,-0.391578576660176));
#539=LINE('',#538,#537);
#540=CARTESIAN_POINT('',(1.2,-2.97433458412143,-0.391578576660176));
#541=VERTEX_POINT('',#540);
#542=EDGE_CURVE('E741',#541,#240,#539,.T.);
#543=ORIENTED_EDGE('',*,*,#542,.F.);
#544=EDGE_CURVE('E1389',#541,#532,#455,.T.);
#545=ORIENTED_EDGE('',*,*,#544,.T.);
#546=EDGE_LOOP('',(#534,#535,#543,#545));
#547=FACE_BOUND('',#546,.T.);
#548=ADVANCED_FACE('F1454',(#547),#433,.T.);
#549=DIRECTION('',(0.,0.866025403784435,0.500000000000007));
#550=VECTOR('',#549,1.);
#551=CARTESIAN_POINT('',(1.2,-2.77163859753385,-1.14805029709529));
#552=LINE('',#551,#550);
#553=CARTESIAN_POINT('',(1.2,-2.77163859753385,-1.14805029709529));
#554=VERTEX_POINT('',#553);
#555=EDGE_CURVE('E735',#258,#554,#552,.T.);
#556=ORIENTED_EDGE('',*,*,#555,.F.);
#557=ORIENTED_EDGE('',*,*,#276,.F.);
#558=DIRECTION('',(0.,-0.866025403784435,-0.500000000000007));
#559=VECTOR('',#558,1.);
#560=CARTESIAN_POINT('',(1.2,-2.38006002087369,-1.82628428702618));
#561=LINE('',#560,#559);
#562=CARTESIAN_POINT('',(1.2,-2.38006002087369,-1.82628428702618));
#563=VERTEX_POINT('',#562);
#564=EDGE_CURVE('E758',#563,#273,#561,.T.);
#565=ORIENTED_EDGE('',*,*,#564,.F.);
#566=EDGE_CURVE('E1395',#563,#554,#455,.T.);
#567=ORIENTED_EDGE('',*,*,#566,.T.);
#568=EDGE_LOOP('',(#556,#557,#565,#567));
#569=FACE_BOUND('',#568,.T.);
#570=ADVANCED_FACE('F1576',(#569),#433,.T.);
#571=DIRECTION('',(0.,0.499999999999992,0.866025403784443));
#572=VECTOR('',#571,1.);
#573=CARTESIAN_POINT('',(1.2,-1.82628428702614,-2.38006002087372));
#574=LINE('',#573,#572);
#575=CARTESIAN_POINT('',(1.2,-1.82628428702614,-2.38006002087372));
#576=VERTEX_POINT('',#575);
#577=EDGE_CURVE('E752',#291,#576,#574,.T.);
#578=ORIENTED_EDGE('',*,*,#577,.F.);
#579=ORIENTED_EDGE('',*,*,#309,.F.);
#580=DIRECTION('',(0.,-0.499999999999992,-0.866025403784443));
#581=VECTOR('',#580,1.);
#582=CARTESIAN_POINT('',(1.2,-1.14805029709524,-2.77163859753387));
#583=LINE('',#582,#581);
#584=CARTESIAN_POINT('',(1.2,-1.14805029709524,-2.77163859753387));
#585=VERTEX_POINT('',#584);
#586=EDGE_CURVE('E775',#585,#306,#583,.T.);
#587=ORIENTED_EDGE('',*,*,#586,.F.);
#588=EDGE_CURVE('E1401',#585,#576,#455,.T.);
#589=ORIENTED_EDGE('',*,*,#588,.T.);
#590=EDGE_LOOP('',(#578,#579,#587,#589));
#591=FACE_BOUND('',#590,.T.);
#592=ADVANCED_FACE('F1411',(#591),#433,.T.);
#593=DIRECTION('',(0.,0.,1.));
#594=VECTOR('',#593,1.);
#595=CARTESIAN_POINT('',(1.2,-0.391578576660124,-2.97433458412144));
#596=LINE('',#595,#594);
#597=CARTESIAN_POINT('',(1.2,-0.391578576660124,-2.97433458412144));
#598=VERTEX_POINT('',#597);
#599=EDGE_CURVE('E769',#328,#598,#596,.T.);
#600=ORIENTED_EDGE('',*,*,#599,.F.);
#601=ORIENTED_EDGE('',*,*,#350,.F.);
#602=DIRECTION('',(0.,0.,-1.));
#603=VECTOR('',#602,1.);
#604=CARTESIAN_POINT('',(1.2,0.391578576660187,-2.97433458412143));
#605=LINE('',#604,#603);
#606=CARTESIAN_POINT('',(1.2,0.391578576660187,-2.97433458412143));
#607=VERTEX_POINT('',#606);
#608=EDGE_CURVE('E792',#607,#347,#605,.T.);
#609=ORIENTED_EDGE('',*,*,#608,.F.);
#610=EDGE_CURVE('E1247',#607,#598,#455,.T.);
#611=ORIENTED_EDGE('',*,*,#610,.T.);
#612=EDGE_LOOP('',(#600,#601,#609,#611));
#613=FACE_BOUND('',#612,.T.);
#614=ADVANCED_FACE('F1320',(#613),#433,.T.);
#615=DIRECTION('',(0.,-0.50000000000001,0.866025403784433));
#616=VECTOR('',#615,1.);
#617=CARTESIAN_POINT('',(1.2,1.1480502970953,-2.77163859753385));
#618=LINE('',#617,#616);
#619=CARTESIAN_POINT('',(1.2,1.1480502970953,-2.77163859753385));
#620=VERTEX_POINT('',#619);
#621=EDGE_CURVE('E786',#365,#620,#618,.T.);
#622=ORIENTED_EDGE('',*,*,#621,.F.);
#623=ORIENTED_EDGE('',*,*,#383,.F.);
#624=DIRECTION('',(0.,0.50000000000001,-0.866025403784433));
#625=VECTOR('',#624,1.);
#626=CARTESIAN_POINT('',(1.2,1.82628428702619,-2.38006002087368));
#627=LINE('',#626,#625);
#628=CARTESIAN_POINT('',(1.2,1.82628428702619,-2.38006002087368));
#629=VERTEX_POINT('',#628);
#630=EDGE_CURVE('E647',#629,#380,#627,.T.);
#631=ORIENTED_EDGE('',*,*,#630,.F.);
#632=EDGE_CURVE('E1243',#629,#620,#455,.T.);
#633=ORIENTED_EDGE('',*,*,#632,.T.);
#634=EDGE_LOOP('',(#622,#623,#631,#633));
#635=FACE_BOUND('',#634,.T.);
#636=ADVANCED_FACE('F1595',(#635),#433,.T.);
#637=DIRECTION('',(0.,-0.866025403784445,0.499999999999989));
#638=VECTOR('',#637,1.);
#639=CARTESIAN_POINT('',(1.2,2.38006002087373,-1.82628428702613));
#640=LINE('',#639,#638);
#641=CARTESIAN_POINT('',(1.2,2.70076760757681,-2.01144489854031));
#642=VERTEX_POINT('',#641);
#643=CARTESIAN_POINT('',(1.2,2.38006002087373,-1.82628428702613));
#644=VERTEX_POINT('',#643);
#645=EDGE_CURVE('E803',#642,#644,#640,.T.);
#646=ORIENTED_EDGE('',*,*,#645,.F.);
#647=CARTESIAN_POINT('',(1.2,3.09234618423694,-1.33321090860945));
#648=VERTEX_POINT('',#647);
#649=EDGE_CURVE('E971',#648,#642,#50,.T.);
#650=ORIENTED_EDGE('',*,*,#649,.F.);
#651=DIRECTION('',(0.,0.866025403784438,-0.500000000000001));
#652=VECTOR('',#651,1.);
#653=CARTESIAN_POINT('',(1.2,2.77163859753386,-1.14805029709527));
#654=LINE('',#653,#652);
#655=CARTESIAN_POINT('',(1.2,2.77163859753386,-1.14805029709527));
#656=VERTEX_POINT('',#655);
#657=EDGE_CURVE('E881',#656,#648,#654,.T.);
#658=ORIENTED_EDGE('',*,*,#657,.F.);
#659=EDGE_CURVE('E1229',#656,#644,#455,.T.);
#660=ORIENTED_EDGE('',*,*,#659,.T.);
#661=EDGE_LOOP('',(#646,#650,#658,#660));
#662=FACE_BOUND('',#661,.T.);
#663=ADVANCED_FACE('F949',(#662),#433,.T.);
#664=DIRECTION('',(0.,0.866025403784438,0.500000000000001));
#665=VECTOR('',#664,1.);
#666=CARTESIAN_POINT('',(1.2,2.3800600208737,1.82628428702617));
#667=LINE('',#666,#665);
#668=CARTESIAN_POINT('',(1.2,2.3800600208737,1.82628428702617));
#669=VERTEX_POINT('',#668);
#670=EDGE_CURVE('E658',#669,#43,#667,.T.);
#671=ORIENTED_EDGE('',*,*,#670,.F.);
#672=CARTESIAN_POINT('',(1.2,2.77163859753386,1.14805029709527));
#673=VERTEX_POINT('',#672);
#674=EDGE_CURVE('E1244',#669,#673,#455,.T.);
#675=ORIENTED_EDGE('',*,*,#674,.T.);
#676=DIRECTION('',(0.,-0.866025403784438,-0.500000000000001));
#677=VECTOR('',#676,1.);
#678=CARTESIAN_POINT('',(1.2,2.77163859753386,1.14805029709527));
#679=LINE('',#678,#677);
#680=EDGE_CURVE('E1267',#52,#673,#679,.T.);
#681=ORIENTED_EDGE('',*,*,#680,.F.);
#682=ORIENTED_EDGE('',*,*,#53,.F.);
#683=EDGE_LOOP('',(#671,#675,#681,#682));
#684=FACE_BOUND('',#683,.T.);
#685=ADVANCED_FACE('F938',(#684),#433,.T.);
#686=CARTESIAN_POINT('',(0.,0.,0.));
#687=DIRECTION('',(-1.,0.,0.));
#688=DIRECTION('',(0.,0.,1.));
#689=AXIS2_PLACEMENT_3D('',#686,#687,#688);
#690=PLANE('',#689);
#691=CARTESIAN_POINT('',(0.,0.,0.));
#692=DIRECTION('',(-1.,0.,0.));
#693=DIRECTION('',(0.,0.,1.));
#694=AXIS2_PLACEMENT_3D('',#691,#692,#693);
#695=CIRCLE('',#694,3.79746);
#696=CARTESIAN_POINT('',(0.,0.,3.79746));
#697=VERTEX_POINT('',#696);
#698=EDGE_CURVE('E1281',#697,#697,#695,.T.);
#699=ORIENTED_EDGE('',*,*,#698,.T.);
#700=EDGE_LOOP('',(#699));
#701=FACE_BOUND('',#700,.T.);
#702=ADVANCED_FACE('F41',(#701),#690,.T.);
#703=CARTESIAN_POINT('',(0.,0.,0.));
#704=DIRECTION('',(-1.,0.,0.));
#705=DIRECTION('',(0.,0.,1.));
#706=AXIS2_PLACEMENT_3D('',#703,#704,#705);
#707=CYLINDRICAL_SURFACE('',#706,3.79746);
#708=CARTESIAN_POINT('',(0.00508000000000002,0.,0.));
#709=DIRECTION('',(-1.,0.,0.));
#710=DIRECTION('',(0.,0.,1.));
#711=AXIS2_PLACEMENT_3D('',#708,#709,#710);
#712=CIRCLE('',#711,3.79746);
#713=CARTESIAN_POINT('',(0.00508000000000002,0.,3.79746));
#714=VERTEX_POINT('',#713);
#715=EDGE_CURVE('E1286',#714,#714,#712,.T.);
#716=ORIENTED_EDGE('',*,*,#715,.T.);
#717=EDGE_LOOP('',(#716));
#718=FACE_BOUND('',#717,.T.);
#719=ORIENTED_EDGE('',*,*,#698,.F.);
#720=EDGE_LOOP('',(#719));
#721=FACE_BOUND('',#720,.T.);
#722=ADVANCED_FACE('F2191',(#718,#721),#707,.T.);
#723=CARTESIAN_POINT('',(0.00508,3.80254,0.));
#724=DIRECTION('',(1.,0.,0.));
#725=DIRECTION('',(0.,0.,-1.));
#726=AXIS2_PLACEMENT_3D('',#723,#724,#725);
#727=PLANE('',#726);
#728=ORIENTED_EDGE('',*,*,#715,.F.);
#729=EDGE_LOOP('',(#728));
#730=FACE_BOUND('',#729,.T.);
#731=CARTESIAN_POINT('',(0.00507999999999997,0.,0.));
#732=DIRECTION('',(-1.,0.,0.));
#733=DIRECTION('',(0.,0.,1.));
#734=AXIS2_PLACEMENT_3D('',#731,#732,#733);
#735=CIRCLE('',#734,3.80254);
#736=CARTESIAN_POINT('',(0.00507999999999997,0.,3.80254));
#737=VERTEX_POINT('',#736);
#738=EDGE_CURVE('E979',#737,#737,#735,.T.);
#739=ORIENTED_EDGE('',*,*,#738,.T.);
#740=EDGE_LOOP('',(#739));
#741=FACE_BOUND('',#740,.T.);
#742=ADVANCED_FACE('F1621',(#730,#741),#727,.F.);
#743=CARTESIAN_POINT('',(0.30254,0.,0.));
#744=DIRECTION('',(-1.,0.,0.));
#745=DIRECTION('',(0.,0.,1.));
#746=AXIS2_PLACEMENT_3D('',#743,#744,#745);
#747=TOROIDAL_SURFACE('',#746,3.80254,0.29746);
#748=CARTESIAN_POINT('',(0.6,0.,0.));
#749=DIRECTION('',(-1.,0.,0.));
#750=DIRECTION('',(0.,0.,1.));
#751=AXIS2_PLACEMENT_3D('',#748,#749,#750);
#752=CIRCLE('',#751,3.80254);
#753=CARTESIAN_POINT('',(0.6,0.,3.80254));
#754=VERTEX_POINT('',#753);
#755=EDGE_CURVE('E976',#754,#754,#752,.T.);
#756=ORIENTED_EDGE('',*,*,#755,.T.);
#757=EDGE_LOOP('',(#756));
#758=FACE_BOUND('',#757,.T.);
#759=ORIENTED_EDGE('',*,*,#738,.F.);
#760=EDGE_LOOP('',(#759));
#761=FACE_BOUND('',#760,.T.);
#762=ADVANCED_FACE('F1617',(#758,#761),#747,.T.);
#763=CARTESIAN_POINT('',(0.6,3.80254,0.));
#764=DIRECTION('',(1.,0.,0.));
#765=DIRECTION('',(0.,0.,-1.));
#766=AXIS2_PLACEMENT_3D('',#763,#764,#765);
#767=PLANE('',#766);
#768=ORIENTED_EDGE('',*,*,#755,.F.);
#769=EDGE_LOOP('',(#768));
#770=FACE_BOUND('',#769,.T.);
#771=ORIENTED_EDGE('',*,*,#370,.T.);
#772=DIRECTION('',(0.,-0.50000000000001,0.866025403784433));
#773=VECTOR('',#772,1.);
#774=CARTESIAN_POINT('',(0.6,1.33321090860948,-3.09234618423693));
#775=LINE('',#774,#773);
#776=CARTESIAN_POINT('',(0.6,1.33321090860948,-3.09234618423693));
#777=VERTEX_POINT('',#776);
#778=EDGE_CURVE('E611',#363,#777,#775,.T.);
#779=ORIENTED_EDGE('',*,*,#778,.T.);
#780=CARTESIAN_POINT('',(0.6,0.,0.));
#781=DIRECTION('',(-1.,0.,0.));
#782=DIRECTION('',(0.,-0.866025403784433,-0.50000000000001));
#783=AXIS2_PLACEMENT_3D('',#780,#781,#782);
#784=CIRCLE('',#783,3.3675);
#785=CARTESIAN_POINT('',(0.6,0.391578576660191,-3.34465580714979));
#786=VERTEX_POINT('',#785);
#787=EDGE_CURVE('E613',#777,#786,#784,.T.);
#788=ORIENTED_EDGE('',*,*,#787,.T.);
#789=DIRECTION('',(0.,0.,-1.));
#790=VECTOR('',#789,1.);
#791=CARTESIAN_POINT('',(0.6,0.391578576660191,-3.34465580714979));
#792=LINE('',#791,#790);
#793=EDGE_CURVE('E617',#786,#332,#792,.T.);
#794=ORIENTED_EDGE('',*,*,#793,.T.);
#795=ORIENTED_EDGE('',*,*,#333,.T.);
#796=DIRECTION('',(0.,0.,1.));
#797=VECTOR('',#796,1.);
#798=CARTESIAN_POINT('',(0.6,-0.391578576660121,-3.34465580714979));
#799=LINE('',#798,#797);
#800=CARTESIAN_POINT('',(0.6,-0.391578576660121,-3.34465580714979));
#801=VERTEX_POINT('',#800);
#802=EDGE_CURVE('E598',#326,#801,#799,.T.);
#803=ORIENTED_EDGE('',*,*,#802,.T.);
#804=CARTESIAN_POINT('',(0.6,0.,0.));
#805=DIRECTION('',(-1.,0.,0.));
#806=DIRECTION('',(0.,-1.,0.));
#807=AXIS2_PLACEMENT_3D('',#804,#805,#806);
#808=CIRCLE('',#807,3.3675);
#809=CARTESIAN_POINT('',(0.6,-1.33321090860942,-3.09234618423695));
#810=VERTEX_POINT('',#809);
#811=EDGE_CURVE('E600',#801,#810,#808,.T.);
#812=ORIENTED_EDGE('',*,*,#811,.T.);
#813=DIRECTION('',(0.,-0.499999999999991,-0.866025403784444));
#814=VECTOR('',#813,1.);
#815=CARTESIAN_POINT('',(0.6,-1.33321090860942,-3.09234618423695));
#816=LINE('',#815,#814);
#817=EDGE_CURVE('E604',#810,#295,#816,.T.);
#818=ORIENTED_EDGE('',*,*,#817,.T.);
#819=ORIENTED_EDGE('',*,*,#296,.T.);
#820=DIRECTION('',(0.,0.499999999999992,0.866025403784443));
#821=VECTOR('',#820,1.);
#822=CARTESIAN_POINT('',(0.6,-2.01144489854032,-2.7007676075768));
#823=LINE('',#822,#821);
#824=CARTESIAN_POINT('',(0.6,-2.01144489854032,-2.7007676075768));
#825=VERTEX_POINT('',#824);
#826=EDGE_CURVE('E585',#289,#825,#823,.T.);
#827=ORIENTED_EDGE('',*,*,#826,.T.);
#828=CARTESIAN_POINT('',(0.6,0.,0.));
#829=DIRECTION('',(-1.,0.,0.));
#830=DIRECTION('',(0.,-0.866025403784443,0.499999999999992));
#831=AXIS2_PLACEMENT_3D('',#828,#829,#830);
#832=CIRCLE('',#831,3.3675);
#833=CARTESIAN_POINT('',(0.6,-2.70076760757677,-2.01144489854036));
#834=VERTEX_POINT('',#833);
#835=EDGE_CURVE('E587',#825,#834,#832,.T.);
#836=ORIENTED_EDGE('',*,*,#835,.T.);
#837=DIRECTION('',(0.,-0.866025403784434,-0.500000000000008));
#838=VECTOR('',#837,1.);
#839=CARTESIAN_POINT('',(0.6,-2.70076760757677,-2.01144489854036));
#840=LINE('',#839,#838);
#841=EDGE_CURVE('E591',#834,#262,#840,.T.);
#842=ORIENTED_EDGE('',*,*,#841,.T.);
#843=ORIENTED_EDGE('',*,*,#263,.T.);
#844=DIRECTION('',(0.,0.866025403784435,0.500000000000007));
#845=VECTOR('',#844,1.);
#846=CARTESIAN_POINT('',(0.6,-3.09234618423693,-1.33321090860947));
#847=LINE('',#846,#845);
#848=CARTESIAN_POINT('',(0.6,-3.09234618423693,-1.33321090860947));
#849=VERTEX_POINT('',#848);
#850=EDGE_CURVE('E572',#256,#849,#847,.T.);
#851=ORIENTED_EDGE('',*,*,#850,.T.);
#852=CARTESIAN_POINT('',(0.6,0.,0.));
#853=DIRECTION('',(-1.,0.,0.));
#854=DIRECTION('',(0.,-0.500000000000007,0.866025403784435));
#855=AXIS2_PLACEMENT_3D('',#852,#853,#854);
#856=CIRCLE('',#855,3.3675);
#857=CARTESIAN_POINT('',(0.6,-3.34465580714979,-0.391578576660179));
#858=VERTEX_POINT('',#857);
#859=EDGE_CURVE('E574',#849,#858,#856,.T.);
#860=ORIENTED_EDGE('',*,*,#859,.T.);
#861=DIRECTION('',(0.,-1.,0.));
#862=VECTOR('',#861,1.);
#863=CARTESIAN_POINT('',(0.6,-3.34465580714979,-0.391578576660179));
#864=LINE('',#863,#862);
#865=EDGE_CURVE('E578',#858,#225,#864,.T.);
#866=ORIENTED_EDGE('',*,*,#865,.T.);
#867=ORIENTED_EDGE('',*,*,#226,.T.);
#868=DIRECTION('',(0.,1.,0.));
#869=VECTOR('',#868,1.);
#870=CARTESIAN_POINT('',(0.6,-3.34465580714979,0.391578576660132));
#871=LINE('',#870,#869);
#872=CARTESIAN_POINT('',(0.6,-3.34465580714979,0.391578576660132));
#873=VERTEX_POINT('',#872);
#874=EDGE_CURVE('E559',#219,#873,#871,.T.);
#875=ORIENTED_EDGE('',*,*,#874,.T.);
#876=CARTESIAN_POINT('',(0.6,0.,0.));
#877=DIRECTION('',(-1.,0.,0.));
#878=DIRECTION('',(0.,0.,1.));
#879=AXIS2_PLACEMENT_3D('',#876,#877,#878);
#880=CIRCLE('',#879,3.3675);
#881=CARTESIAN_POINT('',(0.6,-3.09234618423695,1.33321090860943));
#882=VERTEX_POINT('',#881);
#883=EDGE_CURVE('E561',#873,#882,#880,.T.);
#884=ORIENTED_EDGE('',*,*,#883,.T.);
#885=DIRECTION('',(0.,-0.866025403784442,0.499999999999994));
#886=VECTOR('',#885,1.);
#887=CARTESIAN_POINT('',(0.6,-3.09234618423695,1.33321090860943));
#888=LINE('',#887,#886);
#889=EDGE_CURVE('E565',#882,#188,#888,.T.);
#890=ORIENTED_EDGE('',*,*,#889,.T.);
#891=ORIENTED_EDGE('',*,*,#189,.T.);
#892=DIRECTION('',(0.,0.866025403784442,-0.499999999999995));
#893=VECTOR('',#892,1.);
#894=CARTESIAN_POINT('',(0.6,-2.7007676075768,2.01144489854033));
#895=LINE('',#894,#893);
#896=CARTESIAN_POINT('',(0.6,-2.7007676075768,2.01144489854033));
#897=VERTEX_POINT('',#896);
#898=EDGE_CURVE('E546',#182,#897,#895,.T.);
#899=ORIENTED_EDGE('',*,*,#898,.T.);
#900=CARTESIAN_POINT('',(0.6,0.,0.));
#901=DIRECTION('',(-1.,0.,0.));
#902=DIRECTION('',(0.,0.499999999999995,0.866025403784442));
#903=AXIS2_PLACEMENT_3D('',#900,#901,#902);
#904=CIRCLE('',#903,3.3675);
#905=CARTESIAN_POINT('',(0.6,-2.01144489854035,2.70076760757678));
#906=VERTEX_POINT('',#905);
#907=EDGE_CURVE('E548',#897,#906,#904,.T.);
#908=ORIENTED_EDGE('',*,*,#907,.T.);
#909=DIRECTION('',(0.,-0.500000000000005,0.866025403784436));
#910=VECTOR('',#909,1.);
#911=CARTESIAN_POINT('',(0.6,-2.01144489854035,2.70076760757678));
#912=LINE('',#911,#910);
#913=EDGE_CURVE('E552',#906,#155,#912,.T.);
#914=ORIENTED_EDGE('',*,*,#913,.T.);
#915=ORIENTED_EDGE('',*,*,#156,.T.);
#916=DIRECTION('',(0.,0.500000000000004,-0.866025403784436));
#917=VECTOR('',#916,1.);
#918=CARTESIAN_POINT('',(0.6,-1.33321090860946,3.09234618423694));
#919=LINE('',#918,#917);
#920=CARTESIAN_POINT('',(0.6,-1.33321090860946,3.09234618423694));
#921=VERTEX_POINT('',#920);
#922=EDGE_CURVE('E533',#149,#921,#919,.T.);
#923=ORIENTED_EDGE('',*,*,#922,.T.);
#924=CARTESIAN_POINT('',(0.6,0.,0.));
#925=DIRECTION('',(-1.,0.,0.));
#926=DIRECTION('',(0.,0.866025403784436,0.500000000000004));
#927=AXIS2_PLACEMENT_3D('',#924,#925,#926);
#928=CIRCLE('',#927,3.3675);
#929=CARTESIAN_POINT('',(0.6,-0.391578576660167,3.34465580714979));
#930=VERTEX_POINT('',#929);
#931=EDGE_CURVE('E535',#921,#930,#928,.T.);
#932=ORIENTED_EDGE('',*,*,#931,.T.);
#933=DIRECTION('',(0.,0.,1.));
#934=VECTOR('',#933,1.);
#935=CARTESIAN_POINT('',(0.6,-0.391578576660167,3.34465580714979));
#936=LINE('',#935,#934);
#937=EDGE_CURVE('E539',#930,#118,#936,.T.);
#938=ORIENTED_EDGE('',*,*,#937,.T.);
#939=ORIENTED_EDGE('',*,*,#119,.T.);
#940=DIRECTION('',(0.,0.,-1.));
#941=VECTOR('',#940,1.);
#942=CARTESIAN_POINT('',(0.6,0.391578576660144,3.34465580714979));
#943=LINE('',#942,#941);
#944=CARTESIAN_POINT('',(0.6,0.391578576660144,3.34465580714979));
#945=VERTEX_POINT('',#944);
#946=EDGE_CURVE('E521',#112,#945,#943,.T.);
#947=ORIENTED_EDGE('',*,*,#946,.T.);
#948=CARTESIAN_POINT('',(0.6,0.,0.));
#949=DIRECTION('',(-1.,0.,0.));
#950=DIRECTION('',(0.,1.,0.));
#951=AXIS2_PLACEMENT_3D('',#948,#949,#950);
#952=CIRCLE('',#951,3.3675);
#953=CARTESIAN_POINT('',(0.6,1.33321090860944,3.09234618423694));
#954=VERTEX_POINT('',#953);
#955=EDGE_CURVE('E523',#945,#954,#952,.T.);
#956=ORIENTED_EDGE('',*,*,#955,.T.);
#957=DIRECTION('',(0.,0.499999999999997,0.86602540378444));
#958=VECTOR('',#957,1.);
#959=CARTESIAN_POINT('',(0.6,1.33321090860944,3.09234618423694));
#960=LINE('',#959,#958);
#961=EDGE_CURVE('E527',#954,#81,#960,.T.);
#962=ORIENTED_EDGE('',*,*,#961,.T.);
#963=ORIENTED_EDGE('',*,*,#82,.T.);
#964=DIRECTION('',(0.,-0.499999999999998,-0.86602540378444));
#965=VECTOR('',#964,1.);
#966=CARTESIAN_POINT('',(0.6,2.01144489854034,2.70076760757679));
#967=LINE('',#966,#965);
#968=CARTESIAN_POINT('',(0.6,2.01144489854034,2.70076760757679));
#969=VERTEX_POINT('',#968);
#970=EDGE_CURVE('E491',#75,#969,#967,.T.);
#971=ORIENTED_EDGE('',*,*,#970,.T.);
#972=CARTESIAN_POINT('',(0.6,0.,0.));
#973=DIRECTION('',(-1.,0.,0.));
#974=DIRECTION('',(0.,0.86602540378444,-0.499999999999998));
#975=AXIS2_PLACEMENT_3D('',#972,#973,#974);
#976=CIRCLE('',#975,3.3675);
#977=CARTESIAN_POINT('',(0.6,2.70076760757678,2.01144489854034));
#978=VERTEX_POINT('',#977);
#979=EDGE_CURVE('E497',#969,#978,#976,.T.);
#980=ORIENTED_EDGE('',*,*,#979,.T.);
#981=DIRECTION('',(0.,0.866025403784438,0.500000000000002));
#982=VECTOR('',#981,1.);
#983=CARTESIAN_POINT('',(0.6,2.70076760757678,2.01144489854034));
#984=LINE('',#983,#982);
#985=EDGE_CURVE('E512',#978,#30,#984,.T.);
#986=ORIENTED_EDGE('',*,*,#985,.T.);
#987=ORIENTED_EDGE('',*,*,#33,.T.);
#988=DIRECTION('',(0.,-0.866025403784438,-0.500000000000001));
#989=VECTOR('',#988,1.);
#990=CARTESIAN_POINT('',(0.6,3.09234618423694,1.33321090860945));
#991=LINE('',#990,#989);
#992=CARTESIAN_POINT('',(0.6,3.09234618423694,1.33321090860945));
#993=VERTEX_POINT('',#992);
#994=EDGE_CURVE('E519',#32,#993,#991,.T.);
#995=ORIENTED_EDGE('',*,*,#994,.T.);
#996=CARTESIAN_POINT('',(0.6,0.,0.));
#997=DIRECTION('',(-1.,0.,0.));
#998=DIRECTION('',(0.,0.500000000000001,-0.866025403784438));
#999=AXIS2_PLACEMENT_3D('',#996,#997,#998);
#1000=CIRCLE('',#999,3.3675);
#1001=CARTESIAN_POINT('',(0.6,3.34465580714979,0.391578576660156));
#1002=VERTEX_POINT('',#1001);
#1003=EDGE_CURVE('E637',#993,#1002,#1000,.T.);
#1004=ORIENTED_EDGE('',*,*,#1003,.T.);
#1005=DIRECTION('',(0.,1.,0.));
#1006=VECTOR('',#1005,1.);
#1007=CARTESIAN_POINT('',(0.6,3.34465580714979,0.391578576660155));
#1008=LINE('',#1007,#1006);
#1009=EDGE_CURVE('E640',#1002,#389,#1008,.T.);
#1010=ORIENTED_EDGE('',*,*,#1009,.T.);
#1011=ORIENTED_EDGE('',*,*,#392,.T.);
#1012=DIRECTION('',(0.,-1.,0.));
#1013=VECTOR('',#1012,1.);
#1014=CARTESIAN_POINT('',(0.6,3.34465580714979,-0.391578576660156));
#1015=LINE('',#1014,#1013);
#1016=CARTESIAN_POINT('',(0.6,3.34465580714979,-0.391578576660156));
#1017=VERTEX_POINT('',#1016);
#1018=EDGE_CURVE('E863',#391,#1017,#1015,.T.);
#1019=ORIENTED_EDGE('',*,*,#1018,.T.);
#1020=CARTESIAN_POINT('',(0.6,0.,0.));
#1021=DIRECTION('',(-1.,0.,0.));
#1022=DIRECTION('',(0.,0.,-1.));
#1023=AXIS2_PLACEMENT_3D('',#1020,#1021,#1022);
#1024=CIRCLE('',#1023,3.3675);
#1025=CARTESIAN_POINT('',(0.6,3.09234618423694,-1.33321090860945));
#1026=VERTEX_POINT('',#1025);
#1027=EDGE_CURVE('E871',#1017,#1026,#1024,.T.);
#1028=ORIENTED_EDGE('',*,*,#1027,.T.);
#1029=DIRECTION('',(0.,0.866025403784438,-0.5));
#1030=VECTOR('',#1029,1.);
#1031=CARTESIAN_POINT('',(0.6,3.09234618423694,-1.33321090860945));
#1032=LINE('',#1031,#1030);
#1033=CARTESIAN_POINT('',(0.6,3.41256848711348,-1.51809134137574));
#1034=VERTEX_POINT('',#1033);
#1035=EDGE_CURVE('E874',#1026,#1034,#1032,.T.);
#1036=ORIENTED_EDGE('',*,*,#1035,.T.);
#1037=CARTESIAN_POINT('',(0.6,3.02098991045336,-2.1963253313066));
#1038=VERTEX_POINT('',#1037);
#1039=EDGE_CURVE('E969',#1034,#1038,#28,.T.);
#1040=ORIENTED_EDGE('',*,*,#1039,.T.);
#1041=DIRECTION('',(0.,-0.866025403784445,0.499999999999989));
#1042=VECTOR('',#1041,1.);
#1043=CARTESIAN_POINT('',(0.6,2.70076760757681,-2.01144489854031));
#1044=LINE('',#1043,#1042);
#1045=CARTESIAN_POINT('',(0.6,2.70076760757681,-2.01144489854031));
#1046=VERTEX_POINT('',#1045);
#1047=EDGE_CURVE('E624',#1038,#1046,#1044,.T.);
#1048=ORIENTED_EDGE('',*,*,#1047,.T.);
#1049=CARTESIAN_POINT('',(0.6,0.,0.));
#1050=DIRECTION('',(-1.,0.,0.));
#1051=DIRECTION('',(0.,-0.499999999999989,-0.866025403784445));
#1052=AXIS2_PLACEMENT_3D('',#1049,#1050,#1051);
#1053=CIRCLE('',#1052,3.3675);
#1054=CARTESIAN_POINT('',(0.6,2.01144489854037,-2.70076760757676));
#1055=VERTEX_POINT('',#1054);
#1056=EDGE_CURVE('E626',#1046,#1055,#1053,.T.);
#1057=ORIENTED_EDGE('',*,*,#1056,.T.);
#1058=DIRECTION('',(0.,0.500000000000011,-0.866025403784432));
#1059=VECTOR('',#1058,1.);
#1060=CARTESIAN_POINT('',(0.6,2.01144489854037,-2.70076760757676));
#1061=LINE('',#1060,#1059);
#1062=EDGE_CURVE('E629',#1055,#369,#1061,.T.);
#1063=ORIENTED_EDGE('',*,*,#1062,.T.);
#1064=EDGE_LOOP('',(#771,#779,#788,#794,#795,#803,#812,#818,#819,#827,#836,#842,#843,#851,#860,
#866,#867,#875,#884,#890,#891,#899,#908,#914,#915,#923,#932,#938,#939,#947,#956,#962,#963,#971,
#980,#986,#987,#995,#1004,#1010,#1011,#1019,#1028,#1036,#1040,#1048,#1057,#1063));
#1065=FACE_BOUND('',#1064,.T.);
#1066=ADVANCED_FACE('F494',(#770,#1065),#767,.T.);
#1067=CARTESIAN_POINT('',(0.5998,3.02109658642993,-2.19638692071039));
#1068=CARTESIAN_POINT('',(0.67480487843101,2.98109143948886,-2.17328993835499));
#1069=CARTESIAN_POINT('',(0.74980487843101,2.94107943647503,-2.15018899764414));
#1070=CARTESIAN_POINT('',(0.94994691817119,2.83427974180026,-2.0885281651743));
#1071=CARTESIAN_POINT('',(1.07508025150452,2.76747981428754,-2.04996120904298));
#1072=CARTESIAN_POINT('',(1.2002,2.70066079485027,-2.01138323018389));
#1073=B_SPLINE_CURVE_WITH_KNOTS('',3,(#1067,#1068,#1069,#1070,#1071,#1072),.UNSPECIFIED.,.F.,
.F.,(4,2,4),(0.,0.264266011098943,0.705255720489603),.UNSPECIFIED.);
#1074=EDGE_CURVE('E821',#1038,#642,#1073,.T.);
#1075=ORIENTED_EDGE('',*,*,#1074,.F.);
#1076=ORIENTED_EDGE('',*,*,#1039,.F.);
#1077=CARTESIAN_POINT('',(1.2002,3.0922393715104,-1.33314924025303));
#1078=CARTESIAN_POINT('',(1.07508025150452,3.15905839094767,-1.37172721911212));
#1079=CARTESIAN_POINT('',(0.949946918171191,3.22585831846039,-1.41029417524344));
#1080=CARTESIAN_POINT('',(0.74980487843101,3.33265801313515,-1.47195500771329));
#1081=CARTESIAN_POINT('',(0.67480487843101,3.37267001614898,-1.49505594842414));
#1082=CARTESIAN_POINT('',(0.5998,3.41267516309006,-1.51815293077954));
#1083=B_SPLINE_CURVE_WITH_KNOTS('',3,(#1077,#1078,#1079,#1080,#1081,#1082),.UNSPECIFIED.,.F.,
.F.,(4,2,4),(0.,0.44098970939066,0.705255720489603),.UNSPECIFIED.);
#1084=EDGE_CURVE('E899',#648,#1034,#1083,.T.);
#1085=ORIENTED_EDGE('',*,*,#1084,.F.);
#1086=ORIENTED_EDGE('',*,*,#649,.T.);
#1087=EDGE_LOOP('',(#1075,#1076,#1085,#1086));
#1088=FACE_BOUND('',#1087,.T.);
#1089=ADVANCED_FACE('F828',(#1088),#23,.T.);
#1090=DIRECTION('',(0.,1.,0.));
#1091=VECTOR('',#1090,1.);
#1092=CARTESIAN_POINT('',(1.2,2.97433458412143,0.391578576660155));
#1093=LINE('',#1092,#1091);
#1094=CARTESIAN_POINT('',(1.2,2.97433458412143,0.391578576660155));
#1095=VERTEX_POINT('',#1094);
#1096=EDGE_CURVE('E1265',#1095,#406,#1093,.T.);
#1097=ORIENTED_EDGE('',*,*,#1096,.F.);
#1098=CARTESIAN_POINT('',(1.2,2.97433458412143,-0.391578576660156));
#1099=VERTEX_POINT('',#1098);
#1100=EDGE_CURVE('E1245',#1095,#1099,#455,.T.);
#1101=ORIENTED_EDGE('',*,*,#1100,.T.);
#1102=DIRECTION('',(0.,-1.,0.));
#1103=VECTOR('',#1102,1.);
#1104=CARTESIAN_POINT('',(1.2,2.97433458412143,-0.391578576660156));
#1105=LINE('',#1104,#1103);
#1106=EDGE_CURVE('E887',#410,#1099,#1105,.T.);
#1107=ORIENTED_EDGE('',*,*,#1106,.F.);
#1108=ORIENTED_EDGE('',*,*,#411,.F.);
#1109=EDGE_LOOP('',(#1097,#1101,#1107,#1108));
#1110=FACE_BOUND('',#1109,.T.);
#1111=ADVANCED_FACE('F933',(#1110),#433,.T.);
#1112=CARTESIAN_POINT('',(0.,0.,0.));
#1113=DIRECTION('',(-1.,0.,0.));
#1114=DIRECTION('',(0.,0.,1.));
#1115=AXIS2_PLACEMENT_3D('',#1112,#1113,#1114);
#1116=CYLINDRICAL_SURFACE('',#1115,3.);
#1117=CARTESIAN_POINT('',(17.4094999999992,0.,0.));
#1118=DIRECTION('',(-1.,0.,0.));
#1119=DIRECTION('',(0.,0.,1.));
#1120=AXIS2_PLACEMENT_3D('',#1117,#1118,#1119);
#1121=CIRCLE('',#1120,3.);
#1122=CARTESIAN_POINT('',(17.4094999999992,0.,3.));
#1123=VERTEX_POINT('',#1122);
#1124=EDGE_CURVE('E1250',#1123,#1123,#1121,.T.);
#1125=ORIENTED_EDGE('',*,*,#1124,.T.);
#1126=EDGE_LOOP('',(#1125));
#1127=FACE_BOUND('',#1126,.T.);
#1128=ORIENTED_EDGE('',*,*,#659,.F.);
#1129=DIRECTION('',(1.,0.,0.));
#1130=VECTOR('',#1129,1.);
#1131=CARTESIAN_POINT('',(0.825,2.77163859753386,-1.14805029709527));
#1132=LINE('',#1131,#1130);
#1133=CARTESIAN_POINT('',(0.825,2.77163859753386,-1.14805029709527));
#1134=VERTEX_POINT('',#1133);
#1135=EDGE_CURVE('E892',#1134,#656,#1132,.T.);
#1136=ORIENTED_EDGE('',*,*,#1135,.F.);
#1137=CARTESIAN_POINT('',(0.825,0.,0.));
#1138=DIRECTION('',(-1.,0.,0.));
#1139=DIRECTION('',(0.,0.,-1.));
#1140=AXIS2_PLACEMENT_3D('',#1137,#1138,#1139);
#1141=CIRCLE('',#1140,3.);
#1142=CARTESIAN_POINT('',(0.825,2.97433458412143,-0.391578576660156));
#1143=VERTEX_POINT('',#1142);
#1144=EDGE_CURVE('E883',#1143,#1134,#1141,.T.);
#1145=ORIENTED_EDGE('',*,*,#1144,.F.);
#1146=DIRECTION('',(1.,0.,0.));
#1147=VECTOR('',#1146,1.);
#1148=CARTESIAN_POINT('',(0.825,2.97433458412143,-0.391578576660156));
#1149=LINE('',#1148,#1147);
#1150=EDGE_CURVE('E896',#1143,#1099,#1149,.T.);
#1151=ORIENTED_EDGE('',*,*,#1150,.T.);
#1152=ORIENTED_EDGE('',*,*,#1100,.F.);
#1153=DIRECTION('',(1.,0.,0.));
#1154=VECTOR('',#1153,1.);
#1155=CARTESIAN_POINT('',(0.825,2.97433458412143,0.391578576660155));
#1156=LINE('',#1155,#1154);
#1157=CARTESIAN_POINT('',(0.825,2.97433458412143,0.391578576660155));
#1158=VERTEX_POINT('',#1157);
#1159=EDGE_CURVE('E1271',#1158,#1095,#1156,.T.);
#1160=ORIENTED_EDGE('',*,*,#1159,.F.);
#1161=CARTESIAN_POINT('',(0.825,0.,0.));
#1162=DIRECTION('',(-1.,0.,0.));
#1163=DIRECTION('',(0.,0.500000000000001,-0.866025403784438));
#1164=AXIS2_PLACEMENT_3D('',#1161,#1162,#1163);
#1165=CIRCLE('',#1164,3.);
#1166=CARTESIAN_POINT('',(0.825,2.77163859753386,1.14805029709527));
#1167=VERTEX_POINT('',#1166);
#1168=EDGE_CURVE('E1362',#1167,#1158,#1165,.T.);
#1169=ORIENTED_EDGE('',*,*,#1168,.F.);
#1170=DIRECTION('',(1.,0.,0.));
#1171=VECTOR('',#1170,1.);
#1172=CARTESIAN_POINT('',(0.825,2.77163859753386,1.14805029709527));
#1173=LINE('',#1172,#1171);
#1174=EDGE_CURVE('E1536',#1167,#673,#1173,.T.);
#1175=ORIENTED_EDGE('',*,*,#1174,.T.);
#1176=ORIENTED_EDGE('',*,*,#674,.F.);
#1177=DIRECTION('',(1.,0.,0.));
#1178=VECTOR('',#1177,1.);
#1179=CARTESIAN_POINT('',(0.825,2.3800600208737,1.82628428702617));
#1180=LINE('',#1179,#1178);
#1181=CARTESIAN_POINT('',(0.825,2.3800600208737,1.82628428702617));
#1182=VERTEX_POINT('',#1181);
#1183=EDGE_CURVE('E657',#1182,#669,#1180,.T.);
#1184=ORIENTED_EDGE('',*,*,#1183,.F.);
#1185=CARTESIAN_POINT('',(0.825,0.,0.));
#1186=DIRECTION('',(-1.,0.,0.));
#1187=DIRECTION('',(0.,0.86602540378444,-0.499999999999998));
#1188=AXIS2_PLACEMENT_3D('',#1185,#1186,#1187);
#1189=CIRCLE('',#1188,3.);
#1190=CARTESIAN_POINT('',(0.825,1.82628428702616,2.38006002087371));
#1191=VERTEX_POINT('',#1190);
#1192=EDGE_CURVE('E649',#1191,#1182,#1189,.T.);
#1193=ORIENTED_EDGE('',*,*,#1192,.F.);
#1194=DIRECTION('',(1.,0.,0.));
#1195=VECTOR('',#1194,1.);
#1196=CARTESIAN_POINT('',(0.825,1.82628428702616,2.38006002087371));
#1197=LINE('',#1196,#1195);
#1198=EDGE_CURVE('E54',#1191,#439,#1197,.T.);
#1199=ORIENTED_EDGE('',*,*,#1198,.T.);
#1200=ORIENTED_EDGE('',*,*,#456,.F.);
#1201=DIRECTION('',(1.,0.,0.));
#1202=VECTOR('',#1201,1.);
#1203=CARTESIAN_POINT('',(0.825,1.14805029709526,2.77163859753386));
#1204=LINE('',#1203,#1202);
#1205=CARTESIAN_POINT('',(0.825,1.14805029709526,2.77163859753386));
#1206=VERTEX_POINT('',#1205);
#1207=EDGE_CURVE('E673',#1206,#448,#1204,.T.);
#1208=ORIENTED_EDGE('',*,*,#1207,.F.);
#1209=CARTESIAN_POINT('',(0.825,0.,0.));
#1210=DIRECTION('',(-1.,0.,0.));
#1211=DIRECTION('',(0.,1.,0.));
#1212=AXIS2_PLACEMENT_3D('',#1209,#1210,#1211);
#1213=CIRCLE('',#1212,3.);
#1214=CARTESIAN_POINT('',(0.825,0.391578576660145,2.97433458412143));
#1215=VERTEX_POINT('',#1214);
#1216=EDGE_CURVE('E664',#1215,#1206,#1213,.T.);
#1217=ORIENTED_EDGE('',*,*,#1216,.F.);
#1218=DIRECTION('',(1.,0.,0.));
#1219=VECTOR('',#1218,1.);
#1220=CARTESIAN_POINT('',(0.825,0.391578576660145,2.97433458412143));
#1221=LINE('',#1220,#1219);
#1222=EDGE_CURVE('E61',#1215,#466,#1221,.T.);
#1223=ORIENTED_EDGE('',*,*,#1222,.T.);
#1224=ORIENTED_EDGE('',*,*,#478,.F.);
#1225=DIRECTION('',(1.,0.,0.));
#1226=VECTOR('',#1225,1.);
#1227=CARTESIAN_POINT('',(0.825,-0.391578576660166,2.97433458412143));
#1228=LINE('',#1227,#1226);
#1229=CARTESIAN_POINT('',(0.825,-0.391578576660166,2.97433458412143));
#1230=VERTEX_POINT('',#1229);
#1231=EDGE_CURVE('E689',#1230,#475,#1228,.T.);
#1232=ORIENTED_EDGE('',*,*,#1231,.F.);
#1233=CARTESIAN_POINT('',(0.825,0.,0.));
#1234=DIRECTION('',(-1.,0.,0.));
#1235=DIRECTION('',(0.,0.866025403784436,0.500000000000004));
#1236=AXIS2_PLACEMENT_3D('',#1233,#1234,#1235);
#1237=CIRCLE('',#1236,3.);
#1238=CARTESIAN_POINT('',(0.825,-1.14805029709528,2.77163859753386));
#1239=VERTEX_POINT('',#1238);
#1240=EDGE_CURVE('E680',#1239,#1230,#1237,.T.);
#1241=ORIENTED_EDGE('',*,*,#1240,.F.);
#1242=DIRECTION('',(1.,0.,0.));
#1243=VECTOR('',#1242,1.);
#1244=CARTESIAN_POINT('',(0.825,-1.14805029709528,2.77163859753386));
#1245=LINE('',#1244,#1243);
#1246=EDGE_CURVE('E676',#1239,#488,#1245,.T.);
#1247=ORIENTED_EDGE('',*,*,#1246,.T.);
#1248=ORIENTED_EDGE('',*,*,#500,.F.);
#1249=DIRECTION('',(1.,0.,0.));
#1250=VECTOR('',#1249,1.);
#1251=CARTESIAN_POINT('',(0.825,-1.82628428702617,2.3800600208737));
#1252=LINE('',#1251,#1250);
#1253=CARTESIAN_POINT('',(0.825,-1.82628428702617,2.3800600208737));
#1254=VERTEX_POINT('',#1253);
#1255=EDGE_CURVE('E706',#1254,#497,#1252,.T.);
#1256=ORIENTED_EDGE('',*,*,#1255,.F.);
#1257=CARTESIAN_POINT('',(0.825,0.,0.));
#1258=DIRECTION('',(-1.,0.,0.));
#1259=DIRECTION('',(0.,0.499999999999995,0.866025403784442));
#1260=AXIS2_PLACEMENT_3D('',#1257,#1258,#1259);
#1261=CIRCLE('',#1260,3.);
#1262=CARTESIAN_POINT('',(0.825,-2.38006002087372,1.82628428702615));
#1263=VERTEX_POINT('',#1262);
#1264=EDGE_CURVE('E697',#1263,#1254,#1261,.T.);
#1265=ORIENTED_EDGE('',*,*,#1264,.F.);
#1266=DIRECTION('',(1.,0.,0.));
#1267=VECTOR('',#1266,1.);
#1268=CARTESIAN_POINT('',(0.825,-2.38006002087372,1.82628428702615));
#1269=LINE('',#1268,#1267);
#1270=EDGE_CURVE('E692',#1263,#510,#1269,.T.);
#1271=ORIENTED_EDGE('',*,*,#1270,.T.);
#1272=ORIENTED_EDGE('',*,*,#522,.F.);
#1273=DIRECTION('',(1.,0.,0.));
#1274=VECTOR('',#1273,1.);
#1275=CARTESIAN_POINT('',(0.825,-2.77163859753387,1.14805029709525));
#1276=LINE('',#1275,#1274);
#1277=CARTESIAN_POINT('',(0.825,-2.77163859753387,1.14805029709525));
#1278=VERTEX_POINT('',#1277);
#1279=EDGE_CURVE('E723',#1278,#519,#1276,.T.);
#1280=ORIENTED_EDGE('',*,*,#1279,.F.);
#1281=CARTESIAN_POINT('',(0.825,0.,0.));
#1282=DIRECTION('',(-1.,0.,0.));
#1283=DIRECTION('',(0.,0.,1.));
#1284=AXIS2_PLACEMENT_3D('',#1281,#1282,#1283);
#1285=CIRCLE('',#1284,3.);
#1286=CARTESIAN_POINT('',(0.825,-2.97433458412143,0.391578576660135));
#1287=VERTEX_POINT('',#1286);
#1288=EDGE_CURVE('E714',#1287,#1278,#1285,.T.);
#1289=ORIENTED_EDGE('',*,*,#1288,.F.);
#1290=DIRECTION('',(1.,0.,0.));
#1291=VECTOR('',#1290,1.);
#1292=CARTESIAN_POINT('',(0.825,-2.97433458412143,0.391578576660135));
#1293=LINE('',#1292,#1291);
#1294=EDGE_CURVE('E709',#1287,#532,#1293,.T.);
#1295=ORIENTED_EDGE('',*,*,#1294,.T.);
#1296=ORIENTED_EDGE('',*,*,#544,.F.);
#1297=DIRECTION('',(1.,0.,0.));
#1298=VECTOR('',#1297,1.);
#1299=CARTESIAN_POINT('',(0.825,-2.97433458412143,-0.391578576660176));
#1300=LINE('',#1299,#1298);
#1301=CARTESIAN_POINT('',(0.825,-2.97433458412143,-0.391578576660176));
#1302=VERTEX_POINT('',#1301);
#1303=EDGE_CURVE('E740',#1302,#541,#1300,.T.);
#1304=ORIENTED_EDGE('',*,*,#1303,.F.);
#1305=CARTESIAN_POINT('',(0.825,0.,0.));
#1306=DIRECTION('',(-1.,0.,0.));
#1307=DIRECTION('',(0.,-0.500000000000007,0.866025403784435));
#1308=AXIS2_PLACEMENT_3D('',#1305,#1306,#1307);
#1309=CIRCLE('',#1308,3.);
#1310=CARTESIAN_POINT('',(0.825,-2.77163859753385,-1.14805029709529));
#1311=VERTEX_POINT('',#1310);
#1312=EDGE_CURVE('E731',#1311,#1302,#1309,.T.);
#1313=ORIENTED_EDGE('',*,*,#1312,.F.);
#1314=DIRECTION('',(1.,0.,0.));
#1315=VECTOR('',#1314,1.);
#1316=CARTESIAN_POINT('',(0.825,-2.77163859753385,-1.14805029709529));
#1317=LINE('',#1316,#1315);
#1318=EDGE_CURVE('E726',#1311,#554,#1317,.T.);
#1319=ORIENTED_EDGE('',*,*,#1318,.T.);
#1320=ORIENTED_EDGE('',*,*,#566,.F.);
#1321=DIRECTION('',(1.,0.,0.));
#1322=VECTOR('',#1321,1.);
#1323=CARTESIAN_POINT('',(0.825,-2.38006002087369,-1.82628428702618));
#1324=LINE('',#1323,#1322);
#1325=CARTESIAN_POINT('',(0.825,-2.38006002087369,-1.82628428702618));
#1326=VERTEX_POINT('',#1325);
#1327=EDGE_CURVE('E757',#1326,#563,#1324,.T.);
#1328=ORIENTED_EDGE('',*,*,#1327,.F.);
#1329=CARTESIAN_POINT('',(0.825,0.,0.));
#1330=DIRECTION('',(-1.,0.,0.));
#1331=DIRECTION('',(0.,-0.866025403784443,0.499999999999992));
#1332=AXIS2_PLACEMENT_3D('',#1329,#1330,#1331);
#1333=CIRCLE('',#1332,3.);
#1334=CARTESIAN_POINT('',(0.825,-1.82628428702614,-2.38006002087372));
#1335=VERTEX_POINT('',#1334);
#1336=EDGE_CURVE('E748',#1335,#1326,#1333,.T.);
#1337=ORIENTED_EDGE('',*,*,#1336,.F.);
#1338=DIRECTION('',(1.,0.,0.));
#1339=VECTOR('',#1338,1.);
#1340=CARTESIAN_POINT('',(0.825,-1.82628428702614,-2.38006002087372));
#1341=LINE('',#1340,#1339);
#1342=EDGE_CURVE('E743',#1335,#576,#1341,.T.);
#1343=ORIENTED_EDGE('',*,*,#1342,.T.);
#1344=ORIENTED_EDGE('',*,*,#588,.F.);
#1345=DIRECTION('',(1.,0.,0.));
#1346=VECTOR('',#1345,1.);
#1347=CARTESIAN_POINT('',(0.825,-1.14805029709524,-2.77163859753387));
#1348=LINE('',#1347,#1346);
#1349=CARTESIAN_POINT('',(0.825,-1.14805029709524,-2.77163859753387));
#1350=VERTEX_POINT('',#1349);
#1351=EDGE_CURVE('E774',#1350,#585,#1348,.T.);
#1352=ORIENTED_EDGE('',*,*,#1351,.F.);
#1353=CARTESIAN_POINT('',(0.825,0.,0.));
#1354=DIRECTION('',(-1.,0.,0.));
#1355=DIRECTION('',(0.,-1.,0.));
#1356=AXIS2_PLACEMENT_3D('',#1353,#1354,#1355);
#1357=CIRCLE('',#1356,3.);
#1358=CARTESIAN_POINT('',(0.825,-0.391578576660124,-2.97433458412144));
#1359=VERTEX_POINT('',#1358);
#1360=EDGE_CURVE('E765',#1359,#1350,#1357,.T.);
#1361=ORIENTED_EDGE('',*,*,#1360,.F.);
#1362=DIRECTION('',(1.,0.,0.));
#1363=VECTOR('',#1362,1.);
#1364=CARTESIAN_POINT('',(0.825,-0.391578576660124,-2.97433458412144));
#1365=LINE('',#1364,#1363);
#1366=EDGE_CURVE('E760',#1359,#598,#1365,.T.);
#1367=ORIENTED_EDGE('',*,*,#1366,.T.);
#1368=ORIENTED_EDGE('',*,*,#610,.F.);
#1369=DIRECTION('',(1.,0.,0.));
#1370=VECTOR('',#1369,1.);
#1371=CARTESIAN_POINT('',(0.825,0.391578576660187,-2.97433458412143));
#1372=LINE('',#1371,#1370);
#1373=CARTESIAN_POINT('',(0.825,0.391578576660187,-2.97433458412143));
#1374=VERTEX_POINT('',#1373);
#1375=EDGE_CURVE('E791',#1374,#607,#1372,.T.);
#1376=ORIENTED_EDGE('',*,*,#1375,.F.);
#1377=CARTESIAN_POINT('',(0.825,0.,0.));
#1378=DIRECTION('',(-1.,0.,0.));
#1379=DIRECTION('',(0.,-0.866025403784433,-0.50000000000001));
#1380=AXIS2_PLACEMENT_3D('',#1377,#1378,#1379);
#1381=CIRCLE('',#1380,3.);
#1382=CARTESIAN_POINT('',(0.825,1.1480502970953,-2.77163859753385));
#1383=VERTEX_POINT('',#1382);
#1384=EDGE_CURVE('E782',#1383,#1374,#1381,.T.);
#1385=ORIENTED_EDGE('',*,*,#1384,.F.);
#1386=DIRECTION('',(1.,0.,0.));
#1387=VECTOR('',#1386,1.);
#1388=CARTESIAN_POINT('',(0.825,1.1480502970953,-2.77163859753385));
#1389=LINE('',#1388,#1387);
#1390=EDGE_CURVE('E777',#1383,#620,#1389,.T.);
#1391=ORIENTED_EDGE('',*,*,#1390,.T.);
#1392=ORIENTED_EDGE('',*,*,#632,.F.);
#1393=DIRECTION('',(1.,0.,0.));
#1394=VECTOR('',#1393,1.);
#1395=CARTESIAN_POINT('',(0.825,1.82628428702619,-2.38006002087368));
#1396=LINE('',#1395,#1394);
#1397=CARTESIAN_POINT('',(0.825,1.82628428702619,-2.38006002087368));
#1398=VERTEX_POINT('',#1397);
#1399=EDGE_CURVE('E808',#1398,#629,#1396,.T.);
#1400=ORIENTED_EDGE('',*,*,#1399,.F.);
#1401=CARTESIAN_POINT('',(0.825,0.,0.));
#1402=DIRECTION('',(-1.,0.,0.));
#1403=DIRECTION('',(0.,-0.499999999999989,-0.866025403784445));
#1404=AXIS2_PLACEMENT_3D('',#1401,#1402,#1403);
#1405=CIRCLE('',#1404,3.);
#1406=CARTESIAN_POINT('',(0.825,2.38006002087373,-1.82628428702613));
#1407=VERTEX_POINT('',#1406);
#1408=EDGE_CURVE('E799',#1407,#1398,#1405,.T.);
#1409=ORIENTED_EDGE('',*,*,#1408,.F.);
#1410=DIRECTION('',(1.,0.,0.));
#1411=VECTOR('',#1410,1.);
#1412=CARTESIAN_POINT('',(0.825,2.38006002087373,-1.82628428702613));
#1413=LINE('',#1412,#1411);
#1414=EDGE_CURVE('E794',#1407,#644,#1413,.T.);
#1415=ORIENTED_EDGE('',*,*,#1414,.T.);
#1416=EDGE_LOOP('',(#1128,#1136,#1145,#1151,#1152,#1160,#1169,#1175,#1176,#1184,#1193,#1199,
#1200,#1208,#1217,#1223,#1224,#1232,#1241,#1247,#1248,#1256,#1265,#1271,#1272,#1280,#1289,#1295,
#1296,#1304,#1313,#1319,#1320,#1328,#1337,#1343,#1344,#1352,#1361,#1367,#1368,#1376,#1385,#1391,
#1392,#1400,#1409,#1415));
#1417=FACE_BOUND('',#1416,.T.);
#1418=ADVANCED_FACE('F930',(#1127,#1417),#1116,.T.);
#1419=CARTESIAN_POINT('',(18.,0.,0.));
#1420=DIRECTION('',(-1.,0.,0.));
#1421=DIRECTION('',(0.,0.,1.));
#1422=AXIS2_PLACEMENT_3D('',#1419,#1420,#1421);
#1423=CONICAL_SURFACE('',#1422,2.4095,0.78539816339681);
#1424=ORIENTED_EDGE('',*,*,#1124,.F.);
#1425=EDGE_LOOP('',(#1424));
#1426=FACE_BOUND('',#1425,.T.);
#1427=CARTESIAN_POINT('',(18.,0.,0.));
#1428=DIRECTION('',(-1.,0.,0.));
#1429=DIRECTION('',(0.,0.,1.));
#1430=AXIS2_PLACEMENT_3D('',#1427,#1428,#1429);
#1431=CIRCLE('',#1430,2.4095);
#1432=CARTESIAN_POINT('',(18.,0.,2.4095));
#1433=VERTEX_POINT('',#1432);
#1434=EDGE_CURVE('E1254',#1433,#1433,#1431,.T.);
#1435=ORIENTED_EDGE('',*,*,#1434,.T.);
#1436=EDGE_LOOP('',(#1435));
#1437=FACE_BOUND('',#1436,.T.);
#1438=ADVANCED_FACE('F926',(#1426,#1437),#1423,.T.);
#1439=CARTESIAN_POINT('',(18.,2.4095,0.));
#1440=DIRECTION('',(1.,0.,0.));
#1441=DIRECTION('',(0.,0.,-1.));
#1442=AXIS2_PLACEMENT_3D('',#1439,#1440,#1441);
#1443=PLANE('',#1442);
#1444=ORIENTED_EDGE('',*,*,#1434,.F.);
#1445=EDGE_LOOP('',(#1444));
#1446=FACE_BOUND('',#1445,.T.);
#1447=ADVANCED_FACE('F923',(#1446),#1443,.T.);
#1448=CARTESIAN_POINT('',(0.825,2.97433458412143,-0.391578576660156));
#1449=DIRECTION('',(0.,0.,1.));
#1450=DIRECTION('',(1.,0.,0.));
#1451=AXIS2_PLACEMENT_3D('',#1448,#1449,#1450);
#1452=PLANE('',#1451);
#1453=DIRECTION('',(0.,-1.,0.));
#1454=VECTOR('',#1453,1.);
#1455=CARTESIAN_POINT('',(0.825,2.97433458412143,-0.391578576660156));
#1456=LINE('',#1455,#1454);
#1457=CARTESIAN_POINT('',(0.825,3.34465580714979,-0.391578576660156));
#1458=VERTEX_POINT('',#1457);
#1459=EDGE_CURVE('E890',#1458,#1143,#1456,.T.);
#1460=ORIENTED_EDGE('',*,*,#1459,.F.);
#1461=DIRECTION('',(1.,0.,0.));
#1462=VECTOR('',#1461,1.);
#1463=CARTESIAN_POINT('',(0.6,3.34465580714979,-0.391578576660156));
#1464=LINE('',#1463,#1462);
#1465=EDGE_CURVE('E877',#1017,#1458,#1464,.T.);
#1466=ORIENTED_EDGE('',*,*,#1465,.F.);
#1467=ORIENTED_EDGE('',*,*,#1018,.F.);
#1468=ORIENTED_EDGE('',*,*,#424,.T.);
#1469=ORIENTED_EDGE('',*,*,#1106,.T.);
#1470=ORIENTED_EDGE('',*,*,#1150,.F.);
#1471=EDGE_LOOP('',(#1460,#1466,#1467,#1468,#1469,#1470));
#1472=FACE_BOUND('',#1471,.T.);
#1473=ADVANCED_FACE('F919',(#1472),#1452,.F.);
#1474=CARTESIAN_POINT('',(0.825,2.77163859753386,-1.14805029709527));
#1475=DIRECTION('',(0.,-0.500000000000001,-0.866025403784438));
#1476=DIRECTION('',(0.,0.866025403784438,-0.500000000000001));
#1477=AXIS2_PLACEMENT_3D('',#1474,#1475,#1476);
#1478=PLANE('',#1477);
#1479=ORIENTED_EDGE('',*,*,#657,.T.);
#1480=ORIENTED_EDGE('',*,*,#1084,.T.);
#1481=ORIENTED_EDGE('',*,*,#1035,.F.);
#1482=DIRECTION('',(1.,0.,0.));
#1483=VECTOR('',#1482,1.);
#1484=CARTESIAN_POINT('',(0.6,3.09234618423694,-1.33321090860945));
#1485=LINE('',#1484,#1483);
#1486=CARTESIAN_POINT('',(0.825,3.09234618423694,-1.33321090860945));
#1487=VERTEX_POINT('',#1486);
#1488=EDGE_CURVE('E878',#1026,#1487,#1485,.T.);
#1489=ORIENTED_EDGE('',*,*,#1488,.T.);
#1490=DIRECTION('',(0.,0.866025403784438,-0.500000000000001));
#1491=VECTOR('',#1490,1.);
#1492=CARTESIAN_POINT('',(0.825,2.77163859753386,-1.14805029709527));
#1493=LINE('',#1492,#1491);
#1494=EDGE_CURVE('E886',#1134,#1487,#1493,.T.);
#1495=ORIENTED_EDGE('',*,*,#1494,.F.);
#1496=ORIENTED_EDGE('',*,*,#1135,.T.);
#1497=EDGE_LOOP('',(#1479,#1480,#1481,#1489,#1495,#1496));
#1498=FACE_BOUND('',#1497,.T.);
#1499=ADVANCED_FACE('F914',(#1498),#1478,.F.);
#1500=CARTESIAN_POINT('',(0.825,0.,0.));
#1501=DIRECTION('',(1.,0.,0.));
#1502=DIRECTION('',(0.,0.,-1.));
#1503=AXIS2_PLACEMENT_3D('',#1500,#1501,#1502);
#1504=PLANE('',#1503);
#1505=CARTESIAN_POINT('',(0.825,0.,0.));
#1506=DIRECTION('',(1.,0.,0.));
#1507=DIRECTION('',(0.,0.,-1.));
#1508=AXIS2_PLACEMENT_3D('',#1505,#1506,#1507);
#1509=CIRCLE('',#1508,3.3675);
#1510=EDGE_CURVE('E1277',#1458,#1487,#1509,.F.);
#1511=ORIENTED_EDGE('',*,*,#1510,.F.);
#1512=ORIENTED_EDGE('',*,*,#1459,.T.);
#1513=ORIENTED_EDGE('',*,*,#1144,.T.);
#1514=ORIENTED_EDGE('',*,*,#1494,.T.);
#1515=EDGE_LOOP('',(#1511,#1512,#1513,#1514));
#1516=FACE_BOUND('',#1515,.T.);
#1517=ADVANCED_FACE('F918',(#1516),#1504,.T.);
#1518=CARTESIAN_POINT('',(0.6,0.,0.));
#1519=DIRECTION('',(1.,0.,0.));
#1520=DIRECTION('',(0.,0.,-1.));
#1521=AXIS2_PLACEMENT_3D('',#1518,#1519,#1520);
#1522=CYLINDRICAL_SURFACE('',#1521,3.3675);
#1523=ORIENTED_EDGE('',*,*,#1510,.T.);
#1524=ORIENTED_EDGE('',*,*,#1488,.F.);
#1525=ORIENTED_EDGE('',*,*,#1027,.F.);
#1526=ORIENTED_EDGE('',*,*,#1465,.T.);
#1527=EDGE_LOOP('',(#1523,#1524,#1525,#1526));
#1528=FACE_BOUND('',#1527,.T.);
#1529=ADVANCED_FACE('F850',(#1528),#1522,.T.);
#1530=CARTESIAN_POINT('',(0.825,2.77163859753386,1.14805029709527));
#1531=DIRECTION('',(0.,-0.500000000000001,0.866025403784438));
#1532=DIRECTION('',(0.,-0.866025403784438,-0.500000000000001));
#1533=AXIS2_PLACEMENT_3D('',#1530,#1531,#1532);
#1534=PLANE('',#1533);
#1535=DIRECTION('',(0.,-0.866025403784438,-0.500000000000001));
#1536=VECTOR('',#1535,1.);
#1537=CARTESIAN_POINT('',(0.825,2.77163859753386,1.14805029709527));
#1538=LINE('',#1537,#1536);
#1539=CARTESIAN_POINT('',(0.825,3.09234618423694,1.33321090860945));
#1540=VERTEX_POINT('',#1539);
#1541=EDGE_CURVE('E1531',#1540,#1167,#1538,.T.);
#1542=ORIENTED_EDGE('',*,*,#1541,.F.);
#1543=DIRECTION('',(1.,0.,0.));
#1544=VECTOR('',#1543,1.);
#1545=CARTESIAN_POINT('',(0.6,3.09234618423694,1.33321090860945));
#1546=LINE('',#1545,#1544);
#1547=EDGE_CURVE('E643',#993,#1540,#1546,.T.);
#1548=ORIENTED_EDGE('',*,*,#1547,.F.);
#1549=ORIENTED_EDGE('',*,*,#994,.F.);
#1550=ORIENTED_EDGE('',*,*,#62,.T.);
#1551=ORIENTED_EDGE('',*,*,#680,.T.);
#1552=ORIENTED_EDGE('',*,*,#1174,.F.);
#1553=EDGE_LOOP('',(#1542,#1548,#1549,#1550,#1551,#1552));
#1554=FACE_BOUND('',#1553,.T.);
#1555=ADVANCED_FACE('F846',(#1554),#1534,.F.);
#1556=CARTESIAN_POINT('',(0.825,2.97433458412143,0.391578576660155));
#1557=DIRECTION('',(0.,0.,-1.));
#1558=DIRECTION('',(-1.,0.,0.));
#1559=AXIS2_PLACEMENT_3D('',#1556,#1557,#1558);
#1560=PLANE('',#1559);
#1561=ORIENTED_EDGE('',*,*,#1096,.T.);
#1562=ORIENTED_EDGE('',*,*,#407,.T.);
#1563=ORIENTED_EDGE('',*,*,#1009,.F.);
#1564=DIRECTION('',(1.,0.,0.));
#1565=VECTOR('',#1564,1.);
#1566=CARTESIAN_POINT('',(0.6,3.34465580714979,0.391578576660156));
#1567=LINE('',#1566,#1565);
#1568=CARTESIAN_POINT('',(0.825,3.34465580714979,0.391578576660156));
#1569=VERTEX_POINT('',#1568);
#1570=EDGE_CURVE('E644',#1002,#1569,#1567,.T.);
#1571=ORIENTED_EDGE('',*,*,#1570,.T.);
#1572=DIRECTION('',(0.,1.,0.));
#1573=VECTOR('',#1572,1.);
#1574=CARTESIAN_POINT('',(0.825,2.97433458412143,0.391578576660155));
#1575=LINE('',#1574,#1573);
#1576=EDGE_CURVE('E1529',#1158,#1569,#1575,.T.);
#1577=ORIENTED_EDGE('',*,*,#1576,.F.);
#1578=ORIENTED_EDGE('',*,*,#1159,.T.);
#1579=EDGE_LOOP('',(#1561,#1562,#1563,#1571,#1577,#1578));
#1580=FACE_BOUND('',#1579,.T.);
#1581=ADVANCED_FACE('F844',(#1580),#1560,.F.);
#1582=CARTESIAN_POINT('',(0.825,0.,0.));
#1583=DIRECTION('',(1.,0.,0.));
#1584=DIRECTION('',(0.,0.500000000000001,-0.866025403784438));
#1585=AXIS2_PLACEMENT_3D('',#1582,#1583,#1584);
#1586=PLANE('',#1585);
#1587=CARTESIAN_POINT('',(0.825,0.,0.));
#1588=DIRECTION('',(1.,0.,0.));
#1589=DIRECTION('',(0.,0.,-1.));
#1590=AXIS2_PLACEMENT_3D('',#1587,#1588,#1589);
#1591=CIRCLE('',#1590,3.3675);
#1592=EDGE_CURVE('E1280',#1540,#1569,#1591,.F.);
#1593=ORIENTED_EDGE('',*,*,#1592,.F.);
#1594=ORIENTED_EDGE('',*,*,#1541,.T.);
#1595=ORIENTED_EDGE('',*,*,#1168,.T.);
#1596=ORIENTED_EDGE('',*,*,#1576,.T.);
#1597=EDGE_LOOP('',(#1593,#1594,#1595,#1596));
#1598=FACE_BOUND('',#1597,.T.);
#1599=ADVANCED_FACE('F841',(#1598),#1586,.T.);
#1600=CARTESIAN_POINT('',(0.825,2.38006002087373,-1.82628428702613));
#1601=DIRECTION('',(0.,0.499999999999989,0.866025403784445));
#1602=DIRECTION('',(0.,-0.866025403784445,0.499999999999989));
#1603=AXIS2_PLACEMENT_3D('',#1600,#1601,#1602);
#1604=PLANE('',#1603);
#1605=DIRECTION('',(0.,-0.866025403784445,0.499999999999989));
#1606=VECTOR('',#1605,1.);
#1607=CARTESIAN_POINT('',(0.825,2.38006002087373,-1.82628428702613));
#1608=LINE('',#1607,#1606);
#1609=CARTESIAN_POINT('',(0.825,2.70076760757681,-2.01144489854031));
#1610=VERTEX_POINT('',#1609);
#1611=EDGE_CURVE('E806',#1610,#1407,#1608,.T.);
#1612=ORIENTED_EDGE('',*,*,#1611,.F.);
#1613=DIRECTION('',(1.,0.,0.));
#1614=VECTOR('',#1613,1.);
#1615=CARTESIAN_POINT('',(0.6,2.70076760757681,-2.01144489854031));
#1616=LINE('',#1615,#1614);
#1617=EDGE_CURVE('E632',#1046,#1610,#1616,.T.);
#1618=ORIENTED_EDGE('',*,*,#1617,.F.);
#1619=ORIENTED_EDGE('',*,*,#1047,.F.);
#1620=ORIENTED_EDGE('',*,*,#1074,.T.);
#1621=ORIENTED_EDGE('',*,*,#645,.T.);
#1622=ORIENTED_EDGE('',*,*,#1414,.F.);
#1623=EDGE_LOOP('',(#1612,#1618,#1619,#1620,#1621,#1622));
#1624=FACE_BOUND('',#1623,.T.);
#1625=ADVANCED_FACE('F837',(#1624),#1604,.F.);
#1626=CARTESIAN_POINT('',(0.825,1.82628428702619,-2.38006002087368));
#1627=DIRECTION('',(0.,-0.866025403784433,-0.50000000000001));
#1628=DIRECTION('',(0.,0.50000000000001,-0.866025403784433));
#1629=AXIS2_PLACEMENT_3D('',#1626,#1627,#1628);
#1630=PLANE('',#1629);
#1631=ORIENTED_EDGE('',*,*,#630,.T.);
#1632=ORIENTED_EDGE('',*,*,#381,.T.);
#1633=ORIENTED_EDGE('',*,*,#1062,.F.);
#1634=DIRECTION('',(1.,0.,0.));
#1635=VECTOR('',#1634,1.);
#1636=CARTESIAN_POINT('',(0.6,2.01144489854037,-2.70076760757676));
#1637=LINE('',#1636,#1635);
#1638=CARTESIAN_POINT('',(0.825,2.01144489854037,-2.70076760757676));
#1639=VERTEX_POINT('',#1638);
#1640=EDGE_CURVE('E614',#1055,#1639,#1637,.T.);
#1641=ORIENTED_EDGE('',*,*,#1640,.T.);
#1642=DIRECTION('',(0.,0.50000000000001,-0.866025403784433));
#1643=VECTOR('',#1642,1.);
#1644=CARTESIAN_POINT('',(0.825,1.82628428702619,-2.38006002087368));
#1645=LINE('',#1644,#1643);
#1646=EDGE_CURVE('E802',#1398,#1639,#1645,.T.);
#1647=ORIENTED_EDGE('',*,*,#1646,.F.);
#1648=ORIENTED_EDGE('',*,*,#1399,.T.);
#1649=EDGE_LOOP('',(#1631,#1632,#1633,#1641,#1647,#1648));
#1650=FACE_BOUND('',#1649,.T.);
#1651=ADVANCED_FACE('F832',(#1650),#1630,.F.);
#1652=CARTESIAN_POINT('',(0.825,0.,0.));
#1653=DIRECTION('',(1.,0.,0.));
#1654=DIRECTION('',(0.,-0.499999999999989,-0.866025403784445));
#1655=AXIS2_PLACEMENT_3D('',#1652,#1653,#1654);
#1656=PLANE('',#1655);
#1657=CARTESIAN_POINT('',(0.825,0.,0.));
#1658=DIRECTION('',(1.,0.,0.));
#1659=DIRECTION('',(0.,0.,-1.));
#1660=AXIS2_PLACEMENT_3D('',#1657,#1658,#1659);
#1661=CIRCLE('',#1660,3.3675);
#1662=EDGE_CURVE('E11',#1610,#1639,#1661,.F.);
#1663=ORIENTED_EDGE('',*,*,#1662,.F.);
#1664=ORIENTED_EDGE('',*,*,#1611,.T.);
#1665=ORIENTED_EDGE('',*,*,#1408,.T.);
#1666=ORIENTED_EDGE('',*,*,#1646,.T.);
#1667=EDGE_LOOP('',(#1663,#1664,#1665,#1666));
#1668=FACE_BOUND('',#1667,.T.);
#1669=ADVANCED_FACE('F836',(#1668),#1656,.T.);
#1670=CARTESIAN_POINT('',(0.825,1.1480502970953,-2.77163859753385));
#1671=DIRECTION('',(0.,0.866025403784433,0.50000000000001));
#1672=DIRECTION('',(0.,-0.50000000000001,0.866025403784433));
#1673=AXIS2_PLACEMENT_3D('',#1670,#1671,#1672);
#1674=PLANE('',#1673);
#1675=DIRECTION('',(0.,-0.50000000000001,0.866025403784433));
#1676=VECTOR('',#1675,1.);
#1677=CARTESIAN_POINT('',(0.825,1.1480502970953,-2.77163859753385));
#1678=LINE('',#1677,#1676);
#1679=CARTESIAN_POINT('',(0.825,1.33321090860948,-3.09234618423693));
#1680=VERTEX_POINT('',#1679);
#1681=EDGE_CURVE('E789',#1680,#1383,#1678,.T.);
#1682=ORIENTED_EDGE('',*,*,#1681,.F.);
#1683=DIRECTION('',(1.,0.,0.));
#1684=VECTOR('',#1683,1.);
#1685=CARTESIAN_POINT('',(0.6,1.33321090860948,-3.09234618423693));
#1686=LINE('',#1685,#1684);
#1687=EDGE_CURVE('E620',#777,#1680,#1686,.T.);
#1688=ORIENTED_EDGE('',*,*,#1687,.F.);
#1689=ORIENTED_EDGE('',*,*,#778,.F.);
#1690=ORIENTED_EDGE('',*,*,#366,.T.);
#1691=ORIENTED_EDGE('',*,*,#621,.T.);
#1692=ORIENTED_EDGE('',*,*,#1390,.F.);
#1693=EDGE_LOOP('',(#1682,#1688,#1689,#1690,#1691,#1692));
#1694=FACE_BOUND('',#1693,.T.);
#1695=ADVANCED_FACE('F1198',(#1694),#1674,.F.);
#1696=CARTESIAN_POINT('',(0.825,0.391578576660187,-2.97433458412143));
#1697=DIRECTION('',(0.,-1.,0.));
#1698=DIRECTION('',(0.,0.,-1.));
#1699=AXIS2_PLACEMENT_3D('',#1696,#1697,#1698);
#1700=PLANE('',#1699);
#1701=ORIENTED_EDGE('',*,*,#608,.T.);
#1702=ORIENTED_EDGE('',*,*,#348,.T.);
#1703=ORIENTED_EDGE('',*,*,#793,.F.);
#1704=DIRECTION('',(1.,0.,0.));
#1705=VECTOR('',#1704,1.);
#1706=CARTESIAN_POINT('',(0.6,0.391578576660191,-3.34465580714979));
#1707=LINE('',#1706,#1705);
#1708=CARTESIAN_POINT('',(0.825,0.391578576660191,-3.34465580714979));
#1709=VERTEX_POINT('',#1708);
#1710=EDGE_CURVE('E601',#786,#1709,#1707,.T.);
#1711=ORIENTED_EDGE('',*,*,#1710,.T.);
#1712=DIRECTION('',(0.,0.,-1.));
#1713=VECTOR('',#1712,1.);
#1714=CARTESIAN_POINT('',(0.825,0.391578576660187,-2.97433458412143));
#1715=LINE('',#1714,#1713);
#1716=EDGE_CURVE('E785',#1374,#1709,#1715,.T.);
#1717=ORIENTED_EDGE('',*,*,#1716,.F.);
#1718=ORIENTED_EDGE('',*,*,#1375,.T.);
#1719=EDGE_LOOP('',(#1701,#1702,#1703,#1711,#1717,#1718));
#1720=FACE_BOUND('',#1719,.T.);
#1721=ADVANCED_FACE('F1196',(#1720),#1700,.F.);
#1722=CARTESIAN_POINT('',(0.825,0.,0.));
#1723=DIRECTION('',(1.,0.,0.));
#1724=DIRECTION('',(0.,-0.866025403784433,-0.50000000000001));
#1725=AXIS2_PLACEMENT_3D('',#1722,#1723,#1724);
#1726=PLANE('',#1725);
#1727=CARTESIAN_POINT('',(0.825,0.,0.));
#1728=DIRECTION('',(1.,0.,0.));
#1729=DIRECTION('',(0.,0.,-1.));
#1730=AXIS2_PLACEMENT_3D('',#1727,#1728,#1729);
#1731=CIRCLE('',#1730,3.3675);
#1732=EDGE_CURVE('E47',#1680,#1709,#1731,.F.);
#1733=ORIENTED_EDGE('',*,*,#1732,.F.);
#1734=ORIENTED_EDGE('',*,*,#1681,.T.);
#1735=ORIENTED_EDGE('',*,*,#1384,.T.);
#1736=ORIENTED_EDGE('',*,*,#1716,.T.);
#1737=EDGE_LOOP('',(#1733,#1734,#1735,#1736));
#1738=FACE_BOUND('',#1737,.T.);
#1739=ADVANCED_FACE('F1188',(#1738),#1726,.T.);
#1740=CARTESIAN_POINT('',(0.825,-0.391578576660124,-2.97433458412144));
#1741=DIRECTION('',(0.,1.,0.));
#1742=DIRECTION('',(0.,0.,1.));
#1743=AXIS2_PLACEMENT_3D('',#1740,#1741,#1742);
#1744=PLANE('',#1743);
#1745=DIRECTION('',(0.,0.,1.));
#1746=VECTOR('',#1745,1.);
#1747=CARTESIAN_POINT('',(0.825,-0.391578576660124,-2.97433458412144));
#1748=LINE('',#1747,#1746);
#1749=CARTESIAN_POINT('',(0.825,-0.391578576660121,-3.34465580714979));
#1750=VERTEX_POINT('',#1749);
#1751=EDGE_CURVE('E772',#1750,#1359,#1748,.T.);
#1752=ORIENTED_EDGE('',*,*,#1751,.F.);
#1753=DIRECTION('',(1.,0.,0.));
#1754=VECTOR('',#1753,1.);
#1755=CARTESIAN_POINT('',(0.6,-0.391578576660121,-3.34465580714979));
#1756=LINE('',#1755,#1754);
#1757=EDGE_CURVE('E607',#801,#1750,#1756,.T.);
#1758=ORIENTED_EDGE('',*,*,#1757,.F.);
#1759=ORIENTED_EDGE('',*,*,#802,.F.);
#1760=ORIENTED_EDGE('',*,*,#329,.T.);
#1761=ORIENTED_EDGE('',*,*,#599,.T.);
#1762=ORIENTED_EDGE('',*,*,#1366,.F.);
#1763=EDGE_LOOP('',(#1752,#1758,#1759,#1760,#1761,#1762));
#1764=FACE_BOUND('',#1763,.T.);
#1765=ADVANCED_FACE('F1184',(#1764),#1744,.F.);
#1766=CARTESIAN_POINT('',(0.825,-1.14805029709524,-2.77163859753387));
#1767=DIRECTION('',(0.,-0.866025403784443,0.499999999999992));
#1768=DIRECTION('',(0.,-0.499999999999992,-0.866025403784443));
#1769=AXIS2_PLACEMENT_3D('',#1766,#1767,#1768);
#1770=PLANE('',#1769);
#1771=ORIENTED_EDGE('',*,*,#586,.T.);
#1772=ORIENTED_EDGE('',*,*,#307,.T.);
#1773=ORIENTED_EDGE('',*,*,#817,.F.);
#1774=DIRECTION('',(1.,0.,0.));
#1775=VECTOR('',#1774,1.);
#1776=CARTESIAN_POINT('',(0.6,-1.33321090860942,-3.09234618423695));
#1777=LINE('',#1776,#1775);
#1778=CARTESIAN_POINT('',(0.825,-1.33321090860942,-3.09234618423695));
#1779=VERTEX_POINT('',#1778);
#1780=EDGE_CURVE('E588',#810,#1779,#1777,.T.);
#1781=ORIENTED_EDGE('',*,*,#1780,.T.);
#1782=DIRECTION('',(0.,-0.499999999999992,-0.866025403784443));
#1783=VECTOR('',#1782,1.);
#1784=CARTESIAN_POINT('',(0.825,-1.14805029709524,-2.77163859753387));
#1785=LINE('',#1784,#1783);
#1786=EDGE_CURVE('E768',#1350,#1779,#1785,.T.);
#1787=ORIENTED_EDGE('',*,*,#1786,.F.);
#1788=ORIENTED_EDGE('',*,*,#1351,.T.);
#1789=EDGE_LOOP('',(#1771,#1772,#1773,#1781,#1787,#1788));
#1790=FACE_BOUND('',#1789,.T.);
#1791=ADVANCED_FACE('F1187',(#1790),#1770,.F.);
#1792=CARTESIAN_POINT('',(0.825,0.,0.));
#1793=DIRECTION('',(1.,0.,0.));
#1794=DIRECTION('',(0.,-1.,0.));
#1795=AXIS2_PLACEMENT_3D('',#1792,#1793,#1794);
#1796=PLANE('',#1795);
#1797=CARTESIAN_POINT('',(0.825,0.,0.));
#1798=DIRECTION('',(1.,0.,0.));
#1799=DIRECTION('',(0.,0.,-1.));
#1800=AXIS2_PLACEMENT_3D('',#1797,#1798,#1799);
#1801=CIRCLE('',#1800,3.3675);
#1802=EDGE_CURVE('E1303',#1750,#1779,#1801,.F.);
#1803=ORIENTED_EDGE('',*,*,#1802,.F.);
#1804=ORIENTED_EDGE('',*,*,#1751,.T.);
#1805=ORIENTED_EDGE('',*,*,#1360,.T.);
#1806=ORIENTED_EDGE('',*,*,#1786,.T.);
#1807=EDGE_LOOP('',(#1803,#1804,#1805,#1806));
#1808=FACE_BOUND('',#1807,.T.);
#1809=ADVANCED_FACE('F1154',(#1808),#1796,.T.);
#1810=CARTESIAN_POINT('',(0.825,-1.82628428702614,-2.38006002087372));
#1811=DIRECTION('',(0.,0.866025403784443,-0.499999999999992));
#1812=DIRECTION('',(0.,0.499999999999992,0.866025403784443));
#1813=AXIS2_PLACEMENT_3D('',#1810,#1811,#1812);
#1814=PLANE('',#1813);
#1815=DIRECTION('',(0.,0.499999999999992,0.866025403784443));
#1816=VECTOR('',#1815,1.);
#1817=CARTESIAN_POINT('',(0.825,-1.82628428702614,-2.38006002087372));
#1818=LINE('',#1817,#1816);
#1819=CARTESIAN_POINT('',(0.825,-2.01144489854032,-2.7007676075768));
#1820=VERTEX_POINT('',#1819);
#1821=EDGE_CURVE('E755',#1820,#1335,#1818,.T.);
#1822=ORIENTED_EDGE('',*,*,#1821,.F.);
#1823=DIRECTION('',(1.,0.,0.));
#1824=VECTOR('',#1823,1.);
#1825=CARTESIAN_POINT('',(0.6,-2.01144489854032,-2.7007676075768));
#1826=LINE('',#1825,#1824);
#1827=EDGE_CURVE('E594',#825,#1820,#1826,.T.);
#1828=ORIENTED_EDGE('',*,*,#1827,.F.);
#1829=ORIENTED_EDGE('',*,*,#826,.F.);
#1830=ORIENTED_EDGE('',*,*,#292,.T.);
#1831=ORIENTED_EDGE('',*,*,#577,.T.);
#1832=ORIENTED_EDGE('',*,*,#1342,.F.);
#1833=EDGE_LOOP('',(#1822,#1828,#1829,#1830,#1831,#1832));
#1834=FACE_BOUND('',#1833,.T.);
#1835=ADVANCED_FACE('F1150',(#1834),#1814,.F.);
#1836=CARTESIAN_POINT('',(0.825,-2.38006002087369,-1.82628428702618));
#1837=DIRECTION('',(0.,-0.500000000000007,0.866025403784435));
#1838=DIRECTION('',(0.,-0.866025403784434,-0.500000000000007));
#1839=AXIS2_PLACEMENT_3D('',#1836,#1837,#1838);
#1840=PLANE('',#1839);
#1841=ORIENTED_EDGE('',*,*,#564,.T.);
#1842=ORIENTED_EDGE('',*,*,#274,.T.);
#1843=ORIENTED_EDGE('',*,*,#841,.F.);
#1844=DIRECTION('',(1.,0.,0.));
#1845=VECTOR('',#1844,1.);
#1846=CARTESIAN_POINT('',(0.6,-2.70076760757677,-2.01144489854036));
#1847=LINE('',#1846,#1845);
#1848=CARTESIAN_POINT('',(0.825,-2.70076760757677,-2.01144489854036));
#1849=VERTEX_POINT('',#1848);
#1850=EDGE_CURVE('E575',#834,#1849,#1847,.T.);
#1851=ORIENTED_EDGE('',*,*,#1850,.T.);
#1852=DIRECTION('',(0.,-0.866025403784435,-0.500000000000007));
#1853=VECTOR('',#1852,1.);
#1854=CARTESIAN_POINT('',(0.825,-2.38006002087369,-1.82628428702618));
#1855=LINE('',#1854,#1853);
#1856=EDGE_CURVE('E751',#1326,#1849,#1855,.T.);
#1857=ORIENTED_EDGE('',*,*,#1856,.F.);
#1858=ORIENTED_EDGE('',*,*,#1327,.T.);
#1859=EDGE_LOOP('',(#1841,#1842,#1843,#1851,#1857,#1858));
#1860=FACE_BOUND('',#1859,.T.);
#1861=ADVANCED_FACE('F1148',(#1860),#1840,.F.);
#1862=CARTESIAN_POINT('',(0.825,0.,0.));
#1863=DIRECTION('',(1.,0.,0.));
#1864=DIRECTION('',(0.,-0.866025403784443,0.499999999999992));
#1865=AXIS2_PLACEMENT_3D('',#1862,#1863,#1864);
#1866=PLANE('',#1865);
#1867=CARTESIAN_POINT('',(0.825,0.,0.));
#1868=DIRECTION('',(1.,0.,0.));
#1869=DIRECTION('',(0.,0.,-1.));
#1870=AXIS2_PLACEMENT_3D('',#1867,#1868,#1869);
#1871=CIRCLE('',#1870,3.3675);
#1872=EDGE_CURVE('E1301',#1820,#1849,#1871,.F.);
#1873=ORIENTED_EDGE('',*,*,#1872,.F.);
#1874=ORIENTED_EDGE('',*,*,#1821,.T.);
#1875=ORIENTED_EDGE('',*,*,#1336,.T.);
#1876=ORIENTED_EDGE('',*,*,#1856,.T.);
#1877=EDGE_LOOP('',(#1873,#1874,#1875,#1876));
#1878=FACE_BOUND('',#1877,.T.);
#1879=ADVANCED_FACE('F1140',(#1878),#1866,.T.);
#1880=CARTESIAN_POINT('',(0.825,-2.77163859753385,-1.14805029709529));
#1881=DIRECTION('',(0.,0.500000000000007,-0.866025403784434));
#1882=DIRECTION('',(0.,0.866025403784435,0.500000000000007));
#1883=AXIS2_PLACEMENT_3D('',#1880,#1881,#1882);
#1884=PLANE('',#1883);
#1885=DIRECTION('',(0.,0.866025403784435,0.500000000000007));
#1886=VECTOR('',#1885,1.);
#1887=CARTESIAN_POINT('',(0.825,-2.77163859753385,-1.14805029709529));
#1888=LINE('',#1887,#1886);
#1889=CARTESIAN_POINT('',(0.825,-3.09234618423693,-1.33321090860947));
#1890=VERTEX_POINT('',#1889);
#1891=EDGE_CURVE('E738',#1890,#1311,#1888,.T.);
#1892=ORIENTED_EDGE('',*,*,#1891,.F.);
#1893=DIRECTION('',(1.,0.,0.));
#1894=VECTOR('',#1893,1.);
#1895=CARTESIAN_POINT('',(0.6,-3.09234618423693,-1.33321090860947));
#1896=LINE('',#1895,#1894);
#1897=EDGE_CURVE('E581',#849,#1890,#1896,.T.);
#1898=ORIENTED_EDGE('',*,*,#1897,.F.);
#1899=ORIENTED_EDGE('',*,*,#850,.F.);
#1900=ORIENTED_EDGE('',*,*,#259,.T.);
#1901=ORIENTED_EDGE('',*,*,#555,.T.);
#1902=ORIENTED_EDGE('',*,*,#1318,.F.);
#1903=EDGE_LOOP('',(#1892,#1898,#1899,#1900,#1901,#1902));
#1904=FACE_BOUND('',#1903,.T.);
#1905=ADVANCED_FACE('F1136',(#1904),#1884,.F.);
#1906=CARTESIAN_POINT('',(0.825,-2.97433458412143,-0.391578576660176));
#1907=DIRECTION('',(0.,0.,1.));
#1908=DIRECTION('',(0.,-1.,0.));
#1909=AXIS2_PLACEMENT_3D('',#1906,#1907,#1908);
#1910=PLANE('',#1909);
#1911=ORIENTED_EDGE('',*,*,#542,.T.);
#1912=ORIENTED_EDGE('',*,*,#241,.T.);
#1913=ORIENTED_EDGE('',*,*,#865,.F.);
#1914=DIRECTION('',(1.,0.,0.));
#1915=VECTOR('',#1914,1.);
#1916=CARTESIAN_POINT('',(0.6,-3.34465580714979,-0.391578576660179));
#1917=LINE('',#1916,#1915);
#1918=CARTESIAN_POINT('',(0.825,-3.34465580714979,-0.391578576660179));
#1919=VERTEX_POINT('',#1918);
#1920=EDGE_CURVE('E562',#858,#1919,#1917,.T.);
#1921=ORIENTED_EDGE('',*,*,#1920,.T.);
#1922=DIRECTION('',(0.,-1.,0.));
#1923=VECTOR('',#1922,1.);
#1924=CARTESIAN_POINT('',(0.825,-2.97433458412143,-0.391578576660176));
#1925=LINE('',#1924,#1923);
#1926=EDGE_CURVE('E734',#1302,#1919,#1925,.T.);
#1927=ORIENTED_EDGE('',*,*,#1926,.F.);
#1928=ORIENTED_EDGE('',*,*,#1303,.T.);
#1929=EDGE_LOOP('',(#1911,#1912,#1913,#1921,#1927,#1928));
#1930=FACE_BOUND('',#1929,.T.);
#1931=ADVANCED_FACE('F1139',(#1930),#1910,.F.);
#1932=CARTESIAN_POINT('',(0.825,0.,0.));
#1933=DIRECTION('',(1.,0.,0.));
#1934=DIRECTION('',(0.,-0.500000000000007,0.866025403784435));
#1935=AXIS2_PLACEMENT_3D('',#1932,#1933,#1934);
#1936=PLANE('',#1935);
#1937=CARTESIAN_POINT('',(0.825,0.,0.));
#1938=DIRECTION('',(1.,0.,0.));
#1939=DIRECTION('',(0.,0.,-1.));
#1940=AXIS2_PLACEMENT_3D('',#1937,#1938,#1939);
#1941=CIRCLE('',#1940,3.3675);
#1942=EDGE_CURVE('E1299',#1890,#1919,#1941,.F.);
#1943=ORIENTED_EDGE('',*,*,#1942,.F.);
#1944=ORIENTED_EDGE('',*,*,#1891,.T.);
#1945=ORIENTED_EDGE('',*,*,#1312,.T.);
#1946=ORIENTED_EDGE('',*,*,#1926,.T.);
#1947=EDGE_LOOP('',(#1943,#1944,#1945,#1946));
#1948=FACE_BOUND('',#1947,.T.);
#1949=ADVANCED_FACE('F1106',(#1948),#1936,.T.);
#1950=CARTESIAN_POINT('',(0.825,-2.97433458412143,0.391578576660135));
#1951=DIRECTION('',(0.,0.,-1.));
#1952=DIRECTION('',(0.,1.,0.));
#1953=AXIS2_PLACEMENT_3D('',#1950,#1951,#1952);
#1954=PLANE('',#1953);
#1955=DIRECTION('',(0.,1.,0.));
#1956=VECTOR('',#1955,1.);
#1957=CARTESIAN_POINT('',(0.825,-2.97433458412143,0.391578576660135));
#1958=LINE('',#1957,#1956);
#1959=CARTESIAN_POINT('',(0.825,-3.34465580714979,0.391578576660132));
#1960=VERTEX_POINT('',#1959);
#1961=EDGE_CURVE('E721',#1960,#1287,#1958,.T.);
#1962=ORIENTED_EDGE('',*,*,#1961,.F.);
#1963=DIRECTION('',(1.,0.,0.));
#1964=VECTOR('',#1963,1.);
#1965=CARTESIAN_POINT('',(0.6,-3.34465580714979,0.391578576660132));
#1966=LINE('',#1965,#1964);
#1967=EDGE_CURVE('E568',#873,#1960,#1966,.T.);
#1968=ORIENTED_EDGE('',*,*,#1967,.F.);
#1969=ORIENTED_EDGE('',*,*,#874,.F.);
#1970=ORIENTED_EDGE('',*,*,#222,.T.);
#1971=ORIENTED_EDGE('',*,*,#533,.T.);
#1972=ORIENTED_EDGE('',*,*,#1294,.F.);
#1973=EDGE_LOOP('',(#1962,#1968,#1969,#1970,#1971,#1972));
#1974=FACE_BOUND('',#1973,.T.);
#1975=ADVANCED_FACE('F1102',(#1974),#1954,.F.);
#1976=CARTESIAN_POINT('',(0.825,-2.77163859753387,1.14805029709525));
#1977=DIRECTION('',(0.,0.499999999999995,0.866025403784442));
#1978=DIRECTION('',(0.,-0.866025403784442,0.499999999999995));
#1979=AXIS2_PLACEMENT_3D('',#1976,#1977,#1978);
#1980=PLANE('',#1979);
#1981=ORIENTED_EDGE('',*,*,#520,.T.);
#1982=ORIENTED_EDGE('',*,*,#200,.T.);
#1983=ORIENTED_EDGE('',*,*,#889,.F.);
#1984=DIRECTION('',(1.,0.,0.));
#1985=VECTOR('',#1984,1.);
#1986=CARTESIAN_POINT('',(0.6,-3.09234618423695,1.33321090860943));
#1987=LINE('',#1986,#1985);
#1988=CARTESIAN_POINT('',(0.825,-3.09234618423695,1.33321090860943));
#1989=VERTEX_POINT('',#1988);
#1990=EDGE_CURVE('E549',#882,#1989,#1987,.T.);
#1991=ORIENTED_EDGE('',*,*,#1990,.T.);
#1992=DIRECTION('',(0.,-0.866025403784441,0.499999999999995));
#1993=VECTOR('',#1992,1.);
#1994=CARTESIAN_POINT('',(0.825,-2.77163859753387,1.14805029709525));
#1995=LINE('',#1994,#1993);
#1996=EDGE_CURVE('E717',#1278,#1989,#1995,.T.);
#1997=ORIENTED_EDGE('',*,*,#1996,.F.);
#1998=ORIENTED_EDGE('',*,*,#1279,.T.);
#1999=EDGE_LOOP('',(#1981,#1982,#1983,#1991,#1997,#1998));
#2000=FACE_BOUND('',#1999,.T.);
#2001=ADVANCED_FACE('F1100',(#2000),#1980,.F.);
#2002=CARTESIAN_POINT('',(0.825,0.,0.));
#2003=DIRECTION('',(1.,0.,0.));
#2004=DIRECTION('',(0.,0.,1.));
#2005=AXIS2_PLACEMENT_3D('',#2002,#2003,#2004);
#2006=PLANE('',#2005);
#2007=CARTESIAN_POINT('',(0.825,0.,0.));
#2008=DIRECTION('',(1.,0.,0.));
#2009=DIRECTION('',(0.,0.,-1.));
#2010=AXIS2_PLACEMENT_3D('',#2007,#2008,#2009);
#2011=CIRCLE('',#2010,3.3675);
#2012=EDGE_CURVE('E1297',#1960,#1989,#2011,.F.);
#2013=ORIENTED_EDGE('',*,*,#2012,.F.);
#2014=ORIENTED_EDGE('',*,*,#1961,.T.);
#2015=ORIENTED_EDGE('',*,*,#1288,.T.);
#2016=ORIENTED_EDGE('',*,*,#1996,.T.);
#2017=EDGE_LOOP('',(#2013,#2014,#2015,#2016));
#2018=FACE_BOUND('',#2017,.T.);
#2019=ADVANCED_FACE('F1092',(#2018),#2006,.T.);
#2020=CARTESIAN_POINT('',(0.825,-2.38006002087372,1.82628428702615));
#2021=DIRECTION('',(0.,-0.499999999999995,-0.866025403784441));
#2022=DIRECTION('',(0.,0.866025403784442,-0.499999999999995));
#2023=AXIS2_PLACEMENT_3D('',#2020,#2021,#2022);
#2024=PLANE('',#2023);
#2025=DIRECTION('',(0.,0.866025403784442,-0.499999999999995));
#2026=VECTOR('',#2025,1.);
#2027=CARTESIAN_POINT('',(0.825,-2.38006002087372,1.82628428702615));
#2028=LINE('',#2027,#2026);
#2029=CARTESIAN_POINT('',(0.825,-2.7007676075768,2.01144489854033));
#2030=VERTEX_POINT('',#2029);
#2031=EDGE_CURVE('E704',#2030,#1263,#2028,.T.);
#2032=ORIENTED_EDGE('',*,*,#2031,.F.);
#2033=DIRECTION('',(1.,0.,0.));
#2034=VECTOR('',#2033,1.);
#2035=CARTESIAN_POINT('',(0.6,-2.7007676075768,2.01144489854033));
#2036=LINE('',#2035,#2034);
#2037=EDGE_CURVE('E555',#897,#2030,#2036,.T.);
#2038=ORIENTED_EDGE('',*,*,#2037,.F.);
#2039=ORIENTED_EDGE('',*,*,#898,.F.);
#2040=ORIENTED_EDGE('',*,*,#185,.T.);
#2041=ORIENTED_EDGE('',*,*,#511,.T.);
#2042=ORIENTED_EDGE('',*,*,#1270,.F.);
#2043=EDGE_LOOP('',(#2032,#2038,#2039,#2040,#2041,#2042));
#2044=FACE_BOUND('',#2043,.T.);
#2045=ADVANCED_FACE('F1088',(#2044),#2024,.F.);
#2046=CARTESIAN_POINT('',(0.825,-1.82628428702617,2.3800600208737));
#2047=DIRECTION('',(0.,0.866025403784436,0.500000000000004));
#2048=DIRECTION('',(0.,-0.500000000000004,0.866025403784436));
#2049=AXIS2_PLACEMENT_3D('',#2046,#2047,#2048);
#2050=PLANE('',#2049);
#2051=ORIENTED_EDGE('',*,*,#498,.T.);
#2052=ORIENTED_EDGE('',*,*,#167,.T.);
#2053=ORIENTED_EDGE('',*,*,#913,.F.);
#2054=DIRECTION('',(1.,0.,0.));
#2055=VECTOR('',#2054,1.);
#2056=CARTESIAN_POINT('',(0.6,-2.01144489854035,2.70076760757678));
#2057=LINE('',#2056,#2055);
#2058=CARTESIAN_POINT('',(0.825,-2.01144489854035,2.70076760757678));
#2059=VERTEX_POINT('',#2058);
#2060=EDGE_CURVE('E536',#906,#2059,#2057,.T.);
#2061=ORIENTED_EDGE('',*,*,#2060,.T.);
#2062=DIRECTION('',(0.,-0.500000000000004,0.866025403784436));
#2063=VECTOR('',#2062,1.);
#2064=CARTESIAN_POINT('',(0.825,-1.82628428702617,2.3800600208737));
#2065=LINE('',#2064,#2063);
#2066=EDGE_CURVE('E700',#1254,#2059,#2065,.T.);
#2067=ORIENTED_EDGE('',*,*,#2066,.F.);
#2068=ORIENTED_EDGE('',*,*,#1255,.T.);
#2069=EDGE_LOOP('',(#2051,#2052,#2053,#2061,#2067,#2068));
#2070=FACE_BOUND('',#2069,.T.);
#2071=ADVANCED_FACE('F1091',(#2070),#2050,.F.);
#2072=CARTESIAN_POINT('',(0.825,0.,0.));
#2073=DIRECTION('',(1.,0.,0.));
#2074=DIRECTION('',(0.,0.499999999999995,0.866025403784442));
#2075=AXIS2_PLACEMENT_3D('',#2072,#2073,#2074);
#2076=PLANE('',#2075);
#2077=CARTESIAN_POINT('',(0.825,0.,0.));
#2078=DIRECTION('',(1.,0.,0.));
#2079=DIRECTION('',(0.,0.,-1.));
#2080=AXIS2_PLACEMENT_3D('',#2077,#2078,#2079);
#2081=CIRCLE('',#2080,3.3675);
#2082=EDGE_CURVE('E1295',#2030,#2059,#2081,.F.);
#2083=ORIENTED_EDGE('',*,*,#2082,.F.);
#2084=ORIENTED_EDGE('',*,*,#2031,.T.);
#2085=ORIENTED_EDGE('',*,*,#1264,.T.);
#2086=ORIENTED_EDGE('',*,*,#2066,.T.);
#2087=EDGE_LOOP('',(#2083,#2084,#2085,#2086));
#2088=FACE_BOUND('',#2087,.T.);
#2089=ADVANCED_FACE('F1063',(#2088),#2076,.T.);
#2090=CARTESIAN_POINT('',(0.825,-1.14805029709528,2.77163859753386));
#2091=DIRECTION('',(0.,-0.866025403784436,-0.500000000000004));
#2092=DIRECTION('',(0.,0.500000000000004,-0.866025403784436));
#2093=AXIS2_PLACEMENT_3D('',#2090,#2091,#2092);
#2094=PLANE('',#2093);
#2095=DIRECTION('',(0.,0.500000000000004,-0.866025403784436));
#2096=VECTOR('',#2095,1.);
#2097=CARTESIAN_POINT('',(0.825,-1.14805029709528,2.77163859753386));
#2098=LINE('',#2097,#2096);
#2099=CARTESIAN_POINT('',(0.825,-1.33321090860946,3.09234618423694));
#2100=VERTEX_POINT('',#2099);
#2101=EDGE_CURVE('E687',#2100,#1239,#2098,.T.);
#2102=ORIENTED_EDGE('',*,*,#2101,.F.);
#2103=DIRECTION('',(1.,0.,0.));
#2104=VECTOR('',#2103,1.);
#2105=CARTESIAN_POINT('',(0.6,-1.33321090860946,3.09234618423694));
#2106=LINE('',#2105,#2104);
#2107=EDGE_CURVE('E542',#921,#2100,#2106,.T.);
#2108=ORIENTED_EDGE('',*,*,#2107,.F.);
#2109=ORIENTED_EDGE('',*,*,#922,.F.);
#2110=ORIENTED_EDGE('',*,*,#152,.T.);
#2111=ORIENTED_EDGE('',*,*,#489,.T.);
#2112=ORIENTED_EDGE('',*,*,#1246,.F.);
#2113=EDGE_LOOP('',(#2102,#2108,#2109,#2110,#2111,#2112));
#2114=FACE_BOUND('',#2113,.T.);
#2115=ADVANCED_FACE('F1059',(#2114),#2094,.F.);
#2116=CARTESIAN_POINT('',(0.825,-0.391578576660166,2.97433458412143));
#2117=DIRECTION('',(0.,1.,0.));
#2118=DIRECTION('',(0.,0.,1.));
#2119=AXIS2_PLACEMENT_3D('',#2116,#2117,#2118);
#2120=PLANE('',#2119);
#2121=ORIENTED_EDGE('',*,*,#476,.T.);
#2122=ORIENTED_EDGE('',*,*,#134,.T.);
#2123=ORIENTED_EDGE('',*,*,#937,.F.);
#2124=DIRECTION('',(1.,0.,0.));
#2125=VECTOR('',#2124,1.);
#2126=CARTESIAN_POINT('',(0.6,-0.391578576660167,3.34465580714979));
#2127=LINE('',#2126,#2125);
#2128=CARTESIAN_POINT('',(0.825,-0.391578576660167,3.34465580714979));
#2129=VERTEX_POINT('',#2128);
#2130=EDGE_CURVE('E524',#930,#2129,#2127,.T.);
#2131=ORIENTED_EDGE('',*,*,#2130,.T.);
#2132=DIRECTION('',(0.,0.,1.));
#2133=VECTOR('',#2132,1.);
#2134=CARTESIAN_POINT('',(0.825,-0.391578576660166,2.97433458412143));
#2135=LINE('',#2134,#2133);
#2136=EDGE_CURVE('E683',#1230,#2129,#2135,.T.);
#2137=ORIENTED_EDGE('',*,*,#2136,.F.);
#2138=ORIENTED_EDGE('',*,*,#1231,.T.);
#2139=EDGE_LOOP('',(#2121,#2122,#2123,#2131,#2137,#2138));
#2140=FACE_BOUND('',#2139,.T.);
#2141=ADVANCED_FACE('F1057',(#2140),#2120,.F.);
#2142=CARTESIAN_POINT('',(0.825,0.,0.));
#2143=DIRECTION('',(1.,0.,0.));
#2144=DIRECTION('',(0.,0.866025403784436,0.500000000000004));
#2145=AXIS2_PLACEMENT_3D('',#2142,#2143,#2144);
#2146=PLANE('',#2145);
#2147=CARTESIAN_POINT('',(0.825,0.,0.));
#2148=DIRECTION('',(1.,0.,0.));
#2149=DIRECTION('',(0.,0.,-1.));
#2150=AXIS2_PLACEMENT_3D('',#2147,#2148,#2149);
#2151=CIRCLE('',#2150,3.3675);
#2152=EDGE_CURVE('E1293',#2100,#2129,#2151,.F.);
#2153=ORIENTED_EDGE('',*,*,#2152,.F.);
#2154=ORIENTED_EDGE('',*,*,#2101,.T.);
#2155=ORIENTED_EDGE('',*,*,#1240,.T.);
#2156=ORIENTED_EDGE('',*,*,#2136,.T.);
#2157=EDGE_LOOP('',(#2153,#2154,#2155,#2156));
#2158=FACE_BOUND('',#2157,.T.);
#2159=ADVANCED_FACE('F1055',(#2158),#2146,.T.);
#2160=CARTESIAN_POINT('',(0.825,0.391578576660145,2.97433458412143));
#2161=DIRECTION('',(0.,-1.,0.));
#2162=DIRECTION('',(0.,0.,-1.));
#2163=AXIS2_PLACEMENT_3D('',#2160,#2161,#2162);
#2164=PLANE('',#2163);
#2165=DIRECTION('',(0.,0.,-1.));
#2166=VECTOR('',#2165,1.);
#2167=CARTESIAN_POINT('',(0.825,0.391578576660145,2.97433458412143));
#2168=LINE('',#2167,#2166);
#2169=CARTESIAN_POINT('',(0.825,0.391578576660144,3.34465580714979));
#2170=VERTEX_POINT('',#2169);
#2171=EDGE_CURVE('E671',#2170,#1215,#2168,.T.);
#2172=ORIENTED_EDGE('',*,*,#2171,.F.);
#2173=DIRECTION('',(1.,0.,0.));
#2174=VECTOR('',#2173,1.);
#2175=CARTESIAN_POINT('',(0.6,0.391578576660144,3.34465580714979));
#2176=LINE('',#2175,#2174);
#2177=EDGE_CURVE('E529',#945,#2170,#2176,.T.);
#2178=ORIENTED_EDGE('',*,*,#2177,.F.);
#2179=ORIENTED_EDGE('',*,*,#946,.F.);
#2180=ORIENTED_EDGE('',*,*,#115,.T.);
#2181=ORIENTED_EDGE('',*,*,#467,.T.);
#2182=ORIENTED_EDGE('',*,*,#1222,.F.);
#2183=EDGE_LOOP('',(#2172,#2178,#2179,#2180,#2181,#2182));
#2184=FACE_BOUND('',#2183,.T.);
#2185=ADVANCED_FACE('F1016',(#2184),#2164,.F.);
#2186=CARTESIAN_POINT('',(0.825,1.14805029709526,2.77163859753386));
#2187=DIRECTION('',(0.,0.86602540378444,-0.499999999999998));
#2188=DIRECTION('',(0.,0.499999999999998,0.86602540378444));
#2189=AXIS2_PLACEMENT_3D('',#2186,#2187,#2188);
#2190=PLANE('',#2189);
#2191=ORIENTED_EDGE('',*,*,#449,.T.);
#2192=ORIENTED_EDGE('',*,*,#93,.T.);
#2193=ORIENTED_EDGE('',*,*,#961,.F.);
#2194=DIRECTION('',(1.,0.,0.));
#2195=VECTOR('',#2194,1.);
#2196=CARTESIAN_POINT('',(0.6,1.33321090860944,3.09234618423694));
#2197=LINE('',#2196,#2195);
#2198=CARTESIAN_POINT('',(0.825,1.33321090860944,3.09234618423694));
#2199=VERTEX_POINT('',#2198);
#2200=EDGE_CURVE('E503',#954,#2199,#2197,.T.);
#2201=ORIENTED_EDGE('',*,*,#2200,.T.);
#2202=DIRECTION('',(0.,0.499999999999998,0.86602540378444));
#2203=VECTOR('',#2202,1.);
#2204=CARTESIAN_POINT('',(0.825,1.14805029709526,2.77163859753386));
#2205=LINE('',#2204,#2203);
#2206=EDGE_CURVE('E667',#1206,#2199,#2205,.T.);
#2207=ORIENTED_EDGE('',*,*,#2206,.F.);
#2208=ORIENTED_EDGE('',*,*,#1207,.T.);
#2209=EDGE_LOOP('',(#2191,#2192,#2193,#2201,#2207,#2208));
#2210=FACE_BOUND('',#2209,.T.);
#2211=ADVANCED_FACE('F1023',(#2210),#2190,.F.);
#2212=CARTESIAN_POINT('',(0.825,0.,0.));
#2213=DIRECTION('',(1.,0.,0.));
#2214=DIRECTION('',(0.,1.,0.));
#2215=AXIS2_PLACEMENT_3D('',#2212,#2213,#2214);
#2216=PLANE('',#2215);
#2217=CARTESIAN_POINT('',(0.825,0.,0.));
#2218=DIRECTION('',(1.,0.,0.));
#2219=DIRECTION('',(0.,0.,-1.));
#2220=AXIS2_PLACEMENT_3D('',#2217,#2218,#2219);
#2221=CIRCLE('',#2220,3.3675);
#2222=EDGE_CURVE('E1291',#2170,#2199,#2221,.F.);
#2223=ORIENTED_EDGE('',*,*,#2222,.F.);
#2224=ORIENTED_EDGE('',*,*,#2171,.T.);
#2225=ORIENTED_EDGE('',*,*,#1216,.T.);
#2226=ORIENTED_EDGE('',*,*,#2206,.T.);
#2227=EDGE_LOOP('',(#2223,#2224,#2225,#2226));
#2228=FACE_BOUND('',#2227,.T.);
#2229=ADVANCED_FACE('F1052',(#2228),#2216,.T.);
#2230=CARTESIAN_POINT('',(0.825,1.82628428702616,2.38006002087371));
#2231=DIRECTION('',(0.,-0.86602540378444,0.499999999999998));
#2232=DIRECTION('',(0.,-0.499999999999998,-0.86602540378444));
#2233=AXIS2_PLACEMENT_3D('',#2230,#2231,#2232);
#2234=PLANE('',#2233);
#2235=DIRECTION('',(0.,-0.499999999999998,-0.86602540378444));
#2236=VECTOR('',#2235,1.);
#2237=CARTESIAN_POINT('',(0.825,1.82628428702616,2.38006002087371));
#2238=LINE('',#2237,#2236);
#2239=CARTESIAN_POINT('',(0.825,2.01144489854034,2.70076760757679));
#2240=VERTEX_POINT('',#2239);
#2241=EDGE_CURVE('E508',#2240,#1191,#2238,.T.);
#2242=ORIENTED_EDGE('',*,*,#2241,.F.);
#2243=DIRECTION('',(1.,0.,0.));
#2244=VECTOR('',#2243,1.);
#2245=CARTESIAN_POINT('',(0.6,2.01144489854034,2.70076760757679));
#2246=LINE('',#2245,#2244);
#2247=EDGE_CURVE('E506',#969,#2240,#2246,.T.);
#2248=ORIENTED_EDGE('',*,*,#2247,.F.);
#2249=ORIENTED_EDGE('',*,*,#970,.F.);
#2250=ORIENTED_EDGE('',*,*,#78,.T.);
#2251=ORIENTED_EDGE('',*,*,#440,.T.);
#2252=ORIENTED_EDGE('',*,*,#1198,.F.);
#2253=EDGE_LOOP('',(#2242,#2248,#2249,#2250,#2251,#2252));
#2254=FACE_BOUND('',#2253,.T.);
#2255=ADVANCED_FACE('F507',(#2254),#2234,.F.);
#2256=CARTESIAN_POINT('',(0.825,2.3800600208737,1.82628428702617));
#2257=DIRECTION('',(0.,0.500000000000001,-0.866025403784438));
#2258=DIRECTION('',(0.,0.866025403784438,0.500000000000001));
#2259=AXIS2_PLACEMENT_3D('',#2256,#2257,#2258);
#2260=PLANE('',#2259);
#2261=ORIENTED_EDGE('',*,*,#670,.T.);
#2262=ORIENTED_EDGE('',*,*,#44,.T.);
#2263=ORIENTED_EDGE('',*,*,#985,.F.);
#2264=DIRECTION('',(1.,0.,0.));
#2265=VECTOR('',#2264,1.);
#2266=CARTESIAN_POINT('',(0.6,2.70076760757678,2.01144489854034));
#2267=LINE('',#2266,#2265);
#2268=CARTESIAN_POINT('',(0.825,2.70076760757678,2.01144489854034));
#2269=VERTEX_POINT('',#2268);
#2270=EDGE_CURVE('E511',#978,#2269,#2267,.T.);
#2271=ORIENTED_EDGE('',*,*,#2270,.T.);
#2272=DIRECTION('',(0.,0.866025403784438,0.500000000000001));
#2273=VECTOR('',#2272,1.);
#2274=CARTESIAN_POINT('',(0.825,2.3800600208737,1.82628428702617));
#2275=LINE('',#2274,#2273);
#2276=EDGE_CURVE('E652',#1182,#2269,#2275,.T.);
#2277=ORIENTED_EDGE('',*,*,#2276,.F.);
#2278=ORIENTED_EDGE('',*,*,#1183,.T.);
#2279=EDGE_LOOP('',(#2261,#2262,#2263,#2271,#2277,#2278));
#2280=FACE_BOUND('',#2279,.T.);
#2281=ADVANCED_FACE('F1367',(#2280),#2260,.F.);
#2282=CARTESIAN_POINT('',(0.825,0.,0.));
#2283=DIRECTION('',(1.,0.,0.));
#2284=DIRECTION('',(0.,0.86602540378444,-0.499999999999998));
#2285=AXIS2_PLACEMENT_3D('',#2282,#2283,#2284);
#2286=PLANE('',#2285);
#2287=CARTESIAN_POINT('',(0.825,0.,0.));
#2288=DIRECTION('',(1.,0.,0.));
#2289=DIRECTION('',(0.,0.,-1.));
#2290=AXIS2_PLACEMENT_3D('',#2287,#2288,#2289);
#2291=CIRCLE('',#2290,3.3675);
#2292=EDGE_CURVE('E1283',#2240,#2269,#2291,.F.);
#2293=ORIENTED_EDGE('',*,*,#2292,.F.);
#2294=ORIENTED_EDGE('',*,*,#2241,.T.);
#2295=ORIENTED_EDGE('',*,*,#1192,.T.);
#2296=ORIENTED_EDGE('',*,*,#2276,.T.);
#2297=EDGE_LOOP('',(#2293,#2294,#2295,#2296));
#2298=FACE_BOUND('',#2297,.T.);
#2299=ADVANCED_FACE('F1368',(#2298),#2286,.T.);
#2300=CARTESIAN_POINT('',(0.6,0.,0.));
#2301=DIRECTION('',(1.,0.,0.));
#2302=DIRECTION('',(0.,0.,-1.));
#2303=AXIS2_PLACEMENT_3D('',#2300,#2301,#2302);
#2304=CYLINDRICAL_SURFACE('',#2303,3.3675);
#2305=ORIENTED_EDGE('',*,*,#1592,.T.);
#2306=ORIENTED_EDGE('',*,*,#1570,.F.);
#2307=ORIENTED_EDGE('',*,*,#1003,.F.);
#2308=ORIENTED_EDGE('',*,*,#1547,.T.);
#2309=EDGE_LOOP('',(#2305,#2306,#2307,#2308));
#2310=FACE_BOUND('',#2309,.T.);
#2311=ADVANCED_FACE('F1515',(#2310),#2304,.T.);
#2312=CARTESIAN_POINT('',(0.6,0.,0.));
#2313=DIRECTION('',(1.,0.,0.));
#2314=DIRECTION('',(0.,0.,-1.));
#2315=AXIS2_PLACEMENT_3D('',#2312,#2313,#2314);
#2316=CYLINDRICAL_SURFACE('',#2315,3.3675);
#2317=ORIENTED_EDGE('',*,*,#2292,.T.);
#2318=ORIENTED_EDGE('',*,*,#2270,.F.);
#2319=ORIENTED_EDGE('',*,*,#979,.F.);
#2320=ORIENTED_EDGE('',*,*,#2247,.T.);
#2321=EDGE_LOOP('',(#2317,#2318,#2319,#2320));
#2322=FACE_BOUND('',#2321,.T.);
#2323=ADVANCED_FACE('F514',(#2322),#2316,.T.);
#2324=CARTESIAN_POINT('',(0.6,0.,0.));
#2325=DIRECTION('',(1.,0.,0.));
#2326=DIRECTION('',(0.,0.,-1.));
#2327=AXIS2_PLACEMENT_3D('',#2324,#2325,#2326);
#2328=CYLINDRICAL_SURFACE('',#2327,3.3675);
#2329=ORIENTED_EDGE('',*,*,#2222,.T.);
#2330=ORIENTED_EDGE('',*,*,#2200,.F.);
#2331=ORIENTED_EDGE('',*,*,#955,.F.);
#2332=ORIENTED_EDGE('',*,*,#2177,.T.);
#2333=EDGE_LOOP('',(#2329,#2330,#2331,#2332));
#2334=FACE_BOUND('',#2333,.T.);
#2335=ADVANCED_FACE('F1020',(#2334),#2328,.T.);
#2336=CARTESIAN_POINT('',(0.6,0.,0.));
#2337=DIRECTION('',(1.,0.,0.));
#2338=DIRECTION('',(0.,0.,-1.));
#2339=AXIS2_PLACEMENT_3D('',#2336,#2337,#2338);
#2340=CYLINDRICAL_SURFACE('',#2339,3.3675);
#2341=ORIENTED_EDGE('',*,*,#2152,.T.);
#2342=ORIENTED_EDGE('',*,*,#2130,.F.);
#2343=ORIENTED_EDGE('',*,*,#931,.F.);
#2344=ORIENTED_EDGE('',*,*,#2107,.T.);
#2345=EDGE_LOOP('',(#2341,#2342,#2343,#2344));
#2346=FACE_BOUND('',#2345,.T.);
#2347=ADVANCED_FACE('F1486',(#2346),#2340,.T.);
#2348=CARTESIAN_POINT('',(0.6,0.,0.));
#2349=DIRECTION('',(1.,0.,0.));
#2350=DIRECTION('',(0.,0.,-1.));
#2351=AXIS2_PLACEMENT_3D('',#2348,#2349,#2350);
#2352=CYLINDRICAL_SURFACE('',#2351,3.3675);
#2353=ORIENTED_EDGE('',*,*,#2082,.T.);
#2354=ORIENTED_EDGE('',*,*,#2060,.F.);
#2355=ORIENTED_EDGE('',*,*,#907,.F.);
#2356=ORIENTED_EDGE('',*,*,#2037,.T.);
#2357=EDGE_LOOP('',(#2353,#2354,#2355,#2356));
#2358=FACE_BOUND('',#2357,.T.);
#2359=ADVANCED_FACE('F1488',(#2358),#2352,.T.);
#2360=CARTESIAN_POINT('',(0.6,0.,0.));
#2361=DIRECTION('',(1.,0.,0.));
#2362=DIRECTION('',(0.,0.,-1.));
#2363=AXIS2_PLACEMENT_3D('',#2360,#2361,#2362);
#2364=CYLINDRICAL_SURFACE('',#2363,3.3675);
#2365=ORIENTED_EDGE('',*,*,#2012,.T.);
#2366=ORIENTED_EDGE('',*,*,#1990,.F.);
#2367=ORIENTED_EDGE('',*,*,#883,.F.);
#2368=ORIENTED_EDGE('',*,*,#1967,.T.);
#2369=EDGE_LOOP('',(#2365,#2366,#2367,#2368));
#2370=FACE_BOUND('',#2369,.T.);
#2371=ADVANCED_FACE('F1494',(#2370),#2364,.T.);
#2372=CARTESIAN_POINT('',(0.6,0.,0.));
#2373=DIRECTION('',(1.,0.,0.));
#2374=DIRECTION('',(0.,0.,-1.));
#2375=AXIS2_PLACEMENT_3D('',#2372,#2373,#2374);
#2376=CYLINDRICAL_SURFACE('',#2375,3.3675);
#2377=ORIENTED_EDGE('',*,*,#1942,.T.);
#2378=ORIENTED_EDGE('',*,*,#1920,.F.);
#2379=ORIENTED_EDGE('',*,*,#859,.F.);
#2380=ORIENTED_EDGE('',*,*,#1897,.T.);
#2381=EDGE_LOOP('',(#2377,#2378,#2379,#2380));
#2382=FACE_BOUND('',#2381,.T.);
#2383=ADVANCED_FACE('F1501',(#2382),#2376,.T.);
#2384=CARTESIAN_POINT('',(0.6,0.,0.));
#2385=DIRECTION('',(1.,0.,0.));
#2386=DIRECTION('',(0.,0.,-1.));
#2387=AXIS2_PLACEMENT_3D('',#2384,#2385,#2386);
#2388=CYLINDRICAL_SURFACE('',#2387,3.3675);
#2389=ORIENTED_EDGE('',*,*,#1872,.T.);
#2390=ORIENTED_EDGE('',*,*,#1850,.F.);
#2391=ORIENTED_EDGE('',*,*,#835,.F.);
#2392=ORIENTED_EDGE('',*,*,#1827,.T.);
#2393=EDGE_LOOP('',(#2389,#2390,#2391,#2392));
#2394=FACE_BOUND('',#2393,.T.);
#2395=ADVANCED_FACE('F1504',(#2394),#2388,.T.);
#2396=CARTESIAN_POINT('',(0.6,0.,0.));
#2397=DIRECTION('',(1.,0.,0.));
#2398=DIRECTION('',(0.,0.,-1.));
#2399=AXIS2_PLACEMENT_3D('',#2396,#2397,#2398);
#2400=CYLINDRICAL_SURFACE('',#2399,3.3675);
#2401=ORIENTED_EDGE('',*,*,#1802,.T.);
#2402=ORIENTED_EDGE('',*,*,#1780,.F.);
#2403=ORIENTED_EDGE('',*,*,#811,.F.);
#2404=ORIENTED_EDGE('',*,*,#1757,.T.);
#2405=EDGE_LOOP('',(#2401,#2402,#2403,#2404));
#2406=FACE_BOUND('',#2405,.T.);
#2407=ADVANCED_FACE('F1425',(#2406),#2400,.T.);
#2408=CARTESIAN_POINT('',(0.6,0.,0.));
#2409=DIRECTION('',(1.,0.,0.));
#2410=DIRECTION('',(0.,0.,-1.));
#2411=AXIS2_PLACEMENT_3D('',#2408,#2409,#2410);
#2412=CYLINDRICAL_SURFACE('',#2411,3.3675);
#2413=ORIENTED_EDGE('',*,*,#1732,.T.);
#2414=ORIENTED_EDGE('',*,*,#1710,.F.);
#2415=ORIENTED_EDGE('',*,*,#787,.F.);
#2416=ORIENTED_EDGE('',*,*,#1687,.T.);
#2417=EDGE_LOOP('',(#2413,#2414,#2415,#2416));
#2418=FACE_BOUND('',#2417,.T.);
#2419=ADVANCED_FACE('F1306',(#2418),#2412,.T.);
#2420=CARTESIAN_POINT('',(0.6,0.,0.));
#2421=DIRECTION('',(1.,0.,0.));
#2422=DIRECTION('',(0.,0.,-1.));
#2423=AXIS2_PLACEMENT_3D('',#2420,#2421,#2422);
#2424=CYLINDRICAL_SURFACE('',#2423,3.3675);
#2425=ORIENTED_EDGE('',*,*,#1662,.T.);
#2426=ORIENTED_EDGE('',*,*,#1640,.F.);
#2427=ORIENTED_EDGE('',*,*,#1056,.F.);
#2428=ORIENTED_EDGE('',*,*,#1617,.T.);
#2429=EDGE_LOOP('',(#2425,#2426,#2427,#2428));
#2430=FACE_BOUND('',#2429,.T.);
#2431=ADVANCED_FACE('F1512',(#2430),#2424,.T.);
#2432=CLOSED_SHELL('',(#66,#99,#140,#173,#206,#247,#280,#313,#354,#387,#428,#460,#482,#504,#526,
#548,#570,#592,#614,#636,#663,#685,#702,#722,#742,#762,#1066,#1089,#1111,#1418,#1438,#1447,
#1473,#1499,#1517,#1529,#1555,#1581,#1599,#1625,#1651,#1669,#1695,#1721,#1739,#1765,#1791,#1809,
#1835,#1861,#1879,#1905,#1931,#1949,#1975,#2001,#2019,#2045,#2071,#2089,#2115,#2141,#2159,#2185,
#2211,#2229,#2255,#2281,#2299,#2311,#2323,#2335,#2347,#2359,#2371,#2383,#2395,#2407,#2419,#2431));
#2433=MANIFOLD_SOLID_BREP('B2',#2432);
#2434=ADVANCED_BREP_SHAPE_REPRESENTATION('',(#18,#2433),#14);
#2435=SHAPE_DEFINITION_REPRESENTATION(#9,#2434);
ENDSEC;
END-ISO-10303-21;
